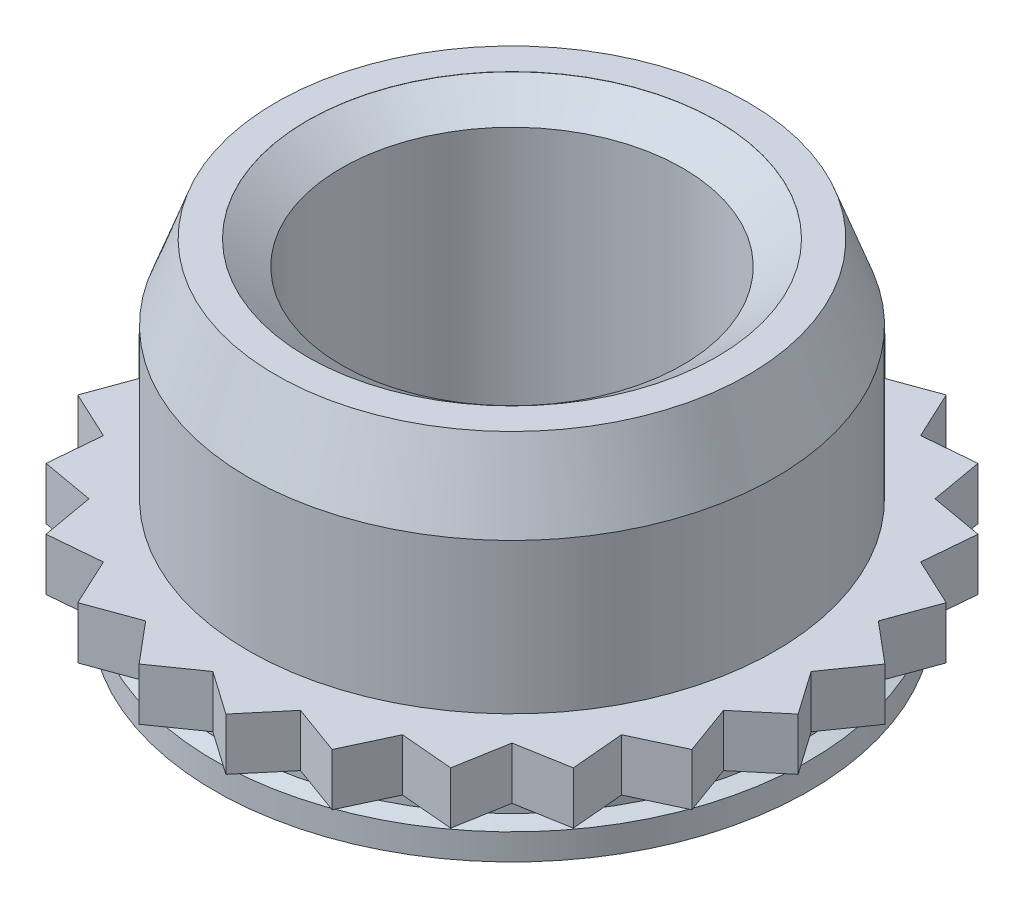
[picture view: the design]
ISO-10303-21;
HEADER;
FILE_DESCRIPTION(('STEP AP214'),'2;1');
FILE_NAME('part.step','',(''),(''),'','','');
FILE_SCHEMA(('AUTOMOTIVE_DESIGN { 1 0 10303 214 1 1 1 1 }'));
ENDSEC;
DATA;
#1=APPLICATION_CONTEXT('core data for automotive mechanical design processes');
#2=APPLICATION_PROTOCOL_DEFINITION('international standard','automotive_design',2000,#1);
#3=PRODUCT_CONTEXT('',#1,'mechanical');
#4=PRODUCT('Part','Part','',(#3));
#5=PRODUCT_RELATED_PRODUCT_CATEGORY('part','',(#4));
#6=PRODUCT_DEFINITION_FORMATION('','',#4);
#7=PRODUCT_DEFINITION_CONTEXT('part definition',#1,'design');
#8=PRODUCT_DEFINITION('design','',#6,#7);
#9=PRODUCT_DEFINITION_SHAPE('','',#8);
#10=(LENGTH_UNIT() NAMED_UNIT(*) SI_UNIT(.MILLI.,.METRE.));
#11=(NAMED_UNIT(*) PLANE_ANGLE_UNIT() SI_UNIT($,.RADIAN.));
#12=(NAMED_UNIT(*) SI_UNIT($,.STERADIAN.) SOLID_ANGLE_UNIT());
#13=UNCERTAINTY_MEASURE_WITH_UNIT(LENGTH_MEASURE(1.E-05),#10,'distance_accuracy_value','');
#14=(GEOMETRIC_REPRESENTATION_CONTEXT(3) GLOBAL_UNCERTAINTY_ASSIGNED_CONTEXT((#13)) GLOBAL_UNIT_ASSIGNED_CONTEXT((#10,
#11,#12)) REPRESENTATION_CONTEXT('',''));
#15=CARTESIAN_POINT('',(0.,0.,0.));
#16=DIRECTION('',(0.,0.,1.));
#17=DIRECTION('',(1.,0.,0.));
#18=AXIS2_PLACEMENT_3D('',#15,#16,#17);
#19=CARTESIAN_POINT('',(0.,0.,0.));
#20=DIRECTION('',(0.,-1.,0.));
#21=DIRECTION('',(0.,0.,-1.));
#22=AXIS2_PLACEMENT_3D('',#19,#20,#21);
#23=CYLINDRICAL_SURFACE('',#22,3.86);
#24=CARTESIAN_POINT('',(0.,2.2,0.));
#25=DIRECTION('',(0.,-1.,0.));
#26=DIRECTION('',(0.,0.,-1.));
#27=AXIS2_PLACEMENT_3D('',#24,#25,#26);
#28=CIRCLE('',#27,3.86);
#29=CARTESIAN_POINT('',(0.,2.2,-3.86));
#30=VERTEX_POINT('',#29);
#31=EDGE_CURVE('E747',#30,#30,#28,.T.);
#32=ORIENTED_EDGE('',*,*,#31,.T.);
#33=EDGE_LOOP('',(#32));
#34=FACE_BOUND('',#33,.T.);
#35=CARTESIAN_POINT('',(0.,0.,0.));
#36=DIRECTION('',(0.,-1.,0.));
#37=DIRECTION('',(0.,0.,-1.));
#38=AXIS2_PLACEMENT_3D('',#35,#36,#37);
#39=CIRCLE('',#38,3.86);
#40=CARTESIAN_POINT('',(0.,0.,-3.86));
#41=VERTEX_POINT('',#40);
#42=EDGE_CURVE('E11',#41,#41,#39,.T.);
#43=ORIENTED_EDGE('',*,*,#42,.F.);
#44=EDGE_LOOP('',(#43));
#45=FACE_BOUND('',#44,.T.);
#46=ADVANCED_FACE('F39',(#34,#45),#23,.T.);
#47=CARTESIAN_POINT('',(4.87,0.,0.));
#48=DIRECTION('',(0.,1.,0.));
#49=DIRECTION('',(0.,0.,1.));
#50=AXIS2_PLACEMENT_3D('',#47,#48,#49);
#51=PLANE('',#50);
#52=DIRECTION('',(0.642592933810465,0.,0.766207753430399));
#53=VECTOR('',#52,1.);
#54=CARTESIAN_POINT('',(-0.635662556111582,0.,4.82833647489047));
#55=LINE('',#54,#53);
#56=CARTESIAN_POINT('',(-1.13440387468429,0.,4.233652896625));
#57=VERTEX_POINT('',#56);
#58=CARTESIAN_POINT('',(-0.635662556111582,0.,4.82833647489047));
#59=VERTEX_POINT('',#58);
#60=EDGE_CURVE('E349',#57,#59,#55,.T.);
#61=ORIENTED_EDGE('',*,*,#60,.T.);
#62=DIRECTION('',(0.819006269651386,0.,-0.573784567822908));
#63=VECTOR('',#62,1.);
#64=CARTESIAN_POINT('',(0.,0.,4.383));
#65=LINE('',#64,#63);
#66=CARTESIAN_POINT('',(0.,0.,4.383));
#67=VERTEX_POINT('',#66);
#68=EDGE_CURVE('E717',#59,#67,#65,.T.);
#69=ORIENTED_EDGE('',*,*,#68,.T.);
#70=DIRECTION('',(0.819006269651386,0.,0.573784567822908));
#71=VECTOR('',#70,1.);
#72=CARTESIAN_POINT('',(0.635662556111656,0.,4.82833647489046));
#73=LINE('',#72,#71);
#74=CARTESIAN_POINT('',(0.635662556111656,0.,4.82833647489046));
#75=VERTEX_POINT('',#74);
#76=EDGE_CURVE('E719',#67,#75,#73,.T.);
#77=ORIENTED_EDGE('',*,*,#76,.T.);
#78=DIRECTION('',(0.642592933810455,0.,-0.766207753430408));
#79=VECTOR('',#78,1.);
#80=CARTESIAN_POINT('',(1.13440387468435,0.,4.23365289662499));
#81=LINE('',#80,#79);
#82=CARTESIAN_POINT('',(1.13440387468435,0.,4.23365289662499));
#83=VERTEX_POINT('',#82);
#84=EDGE_CURVE('E57',#75,#83,#81,.T.);
#85=ORIENTED_EDGE('',*,*,#84,.T.);
#86=DIRECTION('',(0.93960568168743,0.,0.342258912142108));
#87=VECTOR('',#86,1.);
#88=CARTESIAN_POINT('',(1.86366831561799,0.,4.49929332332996));
#89=LINE('',#88,#87);
#90=CARTESIAN_POINT('',(1.86366831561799,0.,4.49929332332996));
#91=VERTEX_POINT('',#90);
#92=EDGE_CURVE('E704',#83,#91,#89,.T.);
#93=ORIENTED_EDGE('',*,*,#92,.T.);
#94=DIRECTION('',(0.422387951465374,0.,-0.906415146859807));
#95=VECTOR('',#94,1.);
#96=CARTESIAN_POINT('',(2.1915,0.,3.79578934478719));
#97=LINE('',#96,#95);
#98=CARTESIAN_POINT('',(2.1915,0.,3.79578934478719));
#99=VERTEX_POINT('',#98);
#100=EDGE_CURVE('E691',#91,#99,#97,.T.);
#101=ORIENTED_EDGE('',*,*,#100,.T.);
#102=DIRECTION('',(0.996172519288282,0.,0.087408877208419));
#103=VECTOR('',#102,1.);
#104=CARTESIAN_POINT('',(2.96466815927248,0.,3.86363076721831));
#105=LINE('',#104,#103);
#106=CARTESIAN_POINT('',(2.96466815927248,0.,3.86363076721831));
#107=VERTEX_POINT('',#106);
#108=EDGE_CURVE('E688',#99,#107,#105,.T.);
#109=ORIENTED_EDGE('',*,*,#108,.T.);
#110=DIRECTION('',(0.173397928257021,0.,-0.984851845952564));
#111=VECTOR('',#110,1.);
#112=CARTESIAN_POINT('',(3.09924902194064,0.,3.09924902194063));
#113=LINE('',#112,#111);
#114=CARTESIAN_POINT('',(3.09924902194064,0.,3.09924902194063));
#115=VERTEX_POINT('',#114);
#116=EDGE_CURVE('E675',#107,#115,#113,.T.);
#117=ORIENTED_EDGE('',*,*,#116,.T.);
#118=DIRECTION('',(0.984851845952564,0.,-0.173397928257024));
#119=VECTOR('',#118,1.);
#120=CARTESIAN_POINT('',(3.86363076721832,0.,2.96466815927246));
#121=LINE('',#120,#119);
#122=CARTESIAN_POINT('',(3.86363076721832,0.,2.96466815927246));
#123=VERTEX_POINT('',#122);
#124=EDGE_CURVE('E674',#115,#123,#121,.T.);
#125=ORIENTED_EDGE('',*,*,#124,.T.);
#126=DIRECTION('',(-0.0874088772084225,0.,-0.996172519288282));
#127=VECTOR('',#126,1.);
#128=CARTESIAN_POINT('',(3.7957893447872,0.,2.19149999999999));
#129=LINE('',#128,#127);
#130=CARTESIAN_POINT('',(3.7957893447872,0.,2.19149999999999));
#131=VERTEX_POINT('',#130);
#132=EDGE_CURVE('E659',#123,#131,#129,.T.);
#133=ORIENTED_EDGE('',*,*,#132,.T.);
#134=DIRECTION('',(0.906415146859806,0.,-0.422387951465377));
#135=VECTOR('',#134,1.);
#136=CARTESIAN_POINT('',(4.49929332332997,0.,1.86366831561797));
#137=LINE('',#136,#135);
#138=CARTESIAN_POINT('',(4.49929332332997,0.,1.86366831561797));
#139=VERTEX_POINT('',#138);
#140=EDGE_CURVE('E658',#131,#139,#137,.T.);
#141=ORIENTED_EDGE('',*,*,#140,.T.);
#142=DIRECTION('',(-0.342258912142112,0.,-0.939605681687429));
#143=VECTOR('',#142,1.);
#144=CARTESIAN_POINT('',(4.23365289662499,0.,1.13440387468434));
#145=LINE('',#144,#143);
#146=CARTESIAN_POINT('',(4.23365289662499,0.,1.13440387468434));
#147=VERTEX_POINT('',#146);
#148=EDGE_CURVE('E639',#139,#147,#145,.T.);
#149=ORIENTED_EDGE('',*,*,#148,.T.);
#150=DIRECTION('',(0.766207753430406,0.,-0.642592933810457));
#151=VECTOR('',#150,1.);
#152=CARTESIAN_POINT('',(4.82833647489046,0.,0.635662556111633));
#153=LINE('',#152,#151);
#154=CARTESIAN_POINT('',(4.82833647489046,0.,0.635662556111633));
#155=VERTEX_POINT('',#154);
#156=EDGE_CURVE('E644',#147,#155,#153,.T.);
#157=ORIENTED_EDGE('',*,*,#156,.T.);
#158=DIRECTION('',(-0.573784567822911,0.,-0.819006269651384));
#159=VECTOR('',#158,1.);
#160=CARTESIAN_POINT('',(4.383,0.,0.));
#161=LINE('',#160,#159);
#162=CARTESIAN_POINT('',(4.383,0.,0.));
#163=VERTEX_POINT('',#162);
#164=EDGE_CURVE('E624',#155,#163,#161,.T.);
#165=ORIENTED_EDGE('',*,*,#164,.T.);
#166=DIRECTION('',(0.573784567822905,0.,-0.819006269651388));
#167=VECTOR('',#166,1.);
#168=CARTESIAN_POINT('',(4.82833647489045,0.,-0.635662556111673));
#169=LINE('',#168,#167);
#170=CARTESIAN_POINT('',(4.82833647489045,0.,-0.635662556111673));
#171=VERTEX_POINT('',#170);
#172=EDGE_CURVE('E630',#163,#171,#169,.T.);
#173=ORIENTED_EDGE('',*,*,#172,.T.);
#174=DIRECTION('',(-0.76620775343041,0.,-0.642592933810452));
#175=VECTOR('',#174,1.);
#176=CARTESIAN_POINT('',(4.23365289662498,0.,-1.13440387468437));
#177=LINE('',#176,#175);
#178=CARTESIAN_POINT('',(4.23365289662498,0.,-1.13440387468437));
#179=VERTEX_POINT('',#178);
#180=EDGE_CURVE('E607',#171,#179,#177,.T.);
#181=ORIENTED_EDGE('',*,*,#180,.T.);
#182=DIRECTION('',(0.342258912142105,0.,-0.939605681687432));
#183=VECTOR('',#182,1.);
#184=CARTESIAN_POINT('',(4.49929332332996,0.,-1.86366831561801));
#185=LINE('',#184,#183);
#186=CARTESIAN_POINT('',(4.49929332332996,0.,-1.86366831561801));
#187=VERTEX_POINT('',#186);
#188=EDGE_CURVE('E614',#179,#187,#185,.T.);
#189=ORIENTED_EDGE('',*,*,#188,.T.);
#190=DIRECTION('',(-0.906415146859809,0.,-0.422387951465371));
#191=VECTOR('',#190,1.);
#192=CARTESIAN_POINT('',(3.79578934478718,0.,-2.19150000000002));
#193=LINE('',#192,#191);
#194=CARTESIAN_POINT('',(3.79578934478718,0.,-2.19150000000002));
#195=VERTEX_POINT('',#194);
#196=EDGE_CURVE('E591',#187,#195,#193,.T.);
#197=ORIENTED_EDGE('',*,*,#196,.T.);
#198=DIRECTION('',(0.0874088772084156,0.,-0.996172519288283));
#199=VECTOR('',#198,1.);
#200=CARTESIAN_POINT('',(3.8636307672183,0.,-2.96466815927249));
#201=LINE('',#200,#199);
#202=CARTESIAN_POINT('',(3.8636307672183,0.,-2.96466815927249));
#203=VERTEX_POINT('',#202);
#204=EDGE_CURVE('E592',#195,#203,#201,.T.);
#205=ORIENTED_EDGE('',*,*,#204,.T.);
#206=DIRECTION('',(-0.984851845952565,0.,-0.173397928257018));
#207=VECTOR('',#206,1.);
#208=CARTESIAN_POINT('',(3.09924902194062,0.,-3.09924902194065));
#209=LINE('',#208,#207);
#210=CARTESIAN_POINT('',(3.09924902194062,0.,-3.09924902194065));
#211=VERTEX_POINT('',#210);
#212=EDGE_CURVE('E577',#203,#211,#209,.T.);
#213=ORIENTED_EDGE('',*,*,#212,.T.);
#214=DIRECTION('',(-0.173397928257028,0.,-0.984851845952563));
#215=VECTOR('',#214,1.);
#216=CARTESIAN_POINT('',(2.96466815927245,0.,-3.86363076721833));
#217=LINE('',#216,#215);
#218=CARTESIAN_POINT('',(2.96466815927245,0.,-3.86363076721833));
#219=VERTEX_POINT('',#218);
#220=EDGE_CURVE('E576',#211,#219,#217,.T.);
#221=ORIENTED_EDGE('',*,*,#220,.T.);
#222=DIRECTION('',(-0.996172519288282,0.,0.0874088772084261));
#223=VECTOR('',#222,1.);
#224=CARTESIAN_POINT('',(2.19149999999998,0.,-3.79578934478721));
#225=LINE('',#224,#223);
#226=CARTESIAN_POINT('',(2.19149999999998,0.,-3.79578934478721));
#227=VERTEX_POINT('',#226);
#228=EDGE_CURVE('E557',#219,#227,#225,.T.);
#229=ORIENTED_EDGE('',*,*,#228,.T.);
#230=DIRECTION('',(-0.42238795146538,0.,-0.906415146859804));
#231=VECTOR('',#230,1.);
#232=CARTESIAN_POINT('',(1.86366831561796,0.,-4.49929332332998));
#233=LINE('',#232,#231);
#234=CARTESIAN_POINT('',(1.86366831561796,0.,-4.49929332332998));
#235=VERTEX_POINT('',#234);
#236=EDGE_CURVE('E563',#227,#235,#233,.T.);
#237=ORIENTED_EDGE('',*,*,#236,.T.);
#238=DIRECTION('',(-0.939605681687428,0.,0.342258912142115));
#239=VECTOR('',#238,1.);
#240=CARTESIAN_POINT('',(1.13440387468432,0.,-4.23365289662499));
#241=LINE('',#240,#239);
#242=CARTESIAN_POINT('',(1.13440387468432,0.,-4.23365289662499));
#243=VERTEX_POINT('',#242);
#244=EDGE_CURVE('E543',#235,#243,#241,.T.);
#245=ORIENTED_EDGE('',*,*,#244,.T.);
#246=DIRECTION('',(-0.64259293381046,0.,-0.766207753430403));
#247=VECTOR('',#246,1.);
#248=CARTESIAN_POINT('',(0.635662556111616,0.,-4.82833647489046));
#249=LINE('',#248,#247);
#250=CARTESIAN_POINT('',(0.635662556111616,0.,-4.82833647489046));
#251=VERTEX_POINT('',#250);
#252=EDGE_CURVE('E546',#243,#251,#249,.T.);
#253=ORIENTED_EDGE('',*,*,#252,.T.);
#254=DIRECTION('',(-0.819006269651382,0.,0.573784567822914));
#255=VECTOR('',#254,1.);
#256=CARTESIAN_POINT('',(0.,0.,-4.383));
#257=LINE('',#256,#255);
#258=CARTESIAN_POINT('',(0.,0.,-4.383));
#259=VERTEX_POINT('',#258);
#260=EDGE_CURVE('E530',#251,#259,#257,.T.);
#261=ORIENTED_EDGE('',*,*,#260,.T.);
#262=DIRECTION('',(-0.81900626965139,0.,-0.573784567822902));
#263=VECTOR('',#262,1.);
#264=CARTESIAN_POINT('',(-0.63566255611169,0.,-4.82833647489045));
#265=LINE('',#264,#263);
#266=CARTESIAN_POINT('',(-0.63566255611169,0.,-4.82833647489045));
#267=VERTEX_POINT('',#266);
#268=EDGE_CURVE('E532',#259,#267,#265,.T.);
#269=ORIENTED_EDGE('',*,*,#268,.T.);
#270=DIRECTION('',(-0.642592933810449,0.,0.766207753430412));
#271=VECTOR('',#270,1.);
#272=CARTESIAN_POINT('',(-1.13440387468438,0.,-4.23365289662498));
#273=LINE('',#272,#271);
#274=CARTESIAN_POINT('',(-1.13440387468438,0.,-4.23365289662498));
#275=VERTEX_POINT('',#274);
#276=EDGE_CURVE('E515',#267,#275,#273,.T.);
#277=ORIENTED_EDGE('',*,*,#276,.T.);
#278=DIRECTION('',(-0.939605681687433,0.,-0.342258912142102));
#279=VECTOR('',#278,1.);
#280=CARTESIAN_POINT('',(-1.86366831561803,0.,-4.49929332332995));
#281=LINE('',#280,#279);
#282=CARTESIAN_POINT('',(-1.86366831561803,0.,-4.49929332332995));
#283=VERTEX_POINT('',#282);
#284=EDGE_CURVE('E513',#275,#283,#281,.T.);
#285=ORIENTED_EDGE('',*,*,#284,.T.);
#286=DIRECTION('',(-0.422387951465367,0.,0.90641514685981));
#287=VECTOR('',#286,1.);
#288=CARTESIAN_POINT('',(-2.19150000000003,0.,-3.79578934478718));
#289=LINE('',#288,#287);
#290=CARTESIAN_POINT('',(-2.19150000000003,0.,-3.79578934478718));
#291=VERTEX_POINT('',#290);
#292=EDGE_CURVE('E496',#283,#291,#289,.T.);
#293=ORIENTED_EDGE('',*,*,#292,.T.);
#294=DIRECTION('',(-0.996172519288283,0.,-0.0874088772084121));
#295=VECTOR('',#294,1.);
#296=CARTESIAN_POINT('',(-2.96466815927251,0.,-3.86363076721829));
#297=LINE('',#296,#295);
#298=CARTESIAN_POINT('',(-2.96466815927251,0.,-3.86363076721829));
#299=VERTEX_POINT('',#298);
#300=EDGE_CURVE('E497',#291,#299,#297,.T.);
#301=ORIENTED_EDGE('',*,*,#300,.T.);
#302=DIRECTION('',(-0.173397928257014,0.,0.984851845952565));
#303=VECTOR('',#302,1.);
#304=CARTESIAN_POINT('',(-3.09924902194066,0.,-3.09924902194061));
#305=LINE('',#304,#303);
#306=CARTESIAN_POINT('',(-3.09924902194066,0.,-3.09924902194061));
#307=VERTEX_POINT('',#306);
#308=EDGE_CURVE('E479',#299,#307,#305,.T.);
#309=ORIENTED_EDGE('',*,*,#308,.T.);
#310=DIRECTION('',(-0.984851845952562,0.,0.173397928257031));
#311=VECTOR('',#310,1.);
#312=CARTESIAN_POINT('',(-3.86363076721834,0.,-2.96466815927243));
#313=LINE('',#312,#311);
#314=CARTESIAN_POINT('',(-3.86363076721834,0.,-2.96466815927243));
#315=VERTEX_POINT('',#314);
#316=EDGE_CURVE('E485',#307,#315,#313,.T.);
#317=ORIENTED_EDGE('',*,*,#316,.T.);
#318=DIRECTION('',(0.0874088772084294,0.,0.996172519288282));
#319=VECTOR('',#318,1.);
#320=CARTESIAN_POINT('',(-3.79578934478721,0.,-2.19149999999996));
#321=LINE('',#320,#319);
#322=CARTESIAN_POINT('',(-3.79578934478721,0.,-2.19149999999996));
#323=VERTEX_POINT('',#322);
#324=EDGE_CURVE('E463',#315,#323,#321,.T.);
#325=ORIENTED_EDGE('',*,*,#324,.T.);
#326=DIRECTION('',(-0.906415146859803,0.,0.422387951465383));
#327=VECTOR('',#326,1.);
#328=CARTESIAN_POINT('',(-4.49929332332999,0.,-1.86366831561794));
#329=LINE('',#328,#327);
#330=CARTESIAN_POINT('',(-4.49929332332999,0.,-1.86366831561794));
#331=VERTEX_POINT('',#330);
#332=EDGE_CURVE('E470',#323,#331,#329,.T.);
#333=ORIENTED_EDGE('',*,*,#332,.T.);
#334=DIRECTION('',(0.342258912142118,0.,0.939605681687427));
#335=VECTOR('',#334,1.);
#336=CARTESIAN_POINT('',(-4.233652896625,0.,-1.13440387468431));
#337=LINE('',#336,#335);
#338=CARTESIAN_POINT('',(-4.233652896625,0.,-1.13440387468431));
#339=VERTEX_POINT('',#338);
#340=EDGE_CURVE('E449',#331,#339,#337,.T.);
#341=ORIENTED_EDGE('',*,*,#340,.T.);
#342=DIRECTION('',(-0.766207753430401,0.,0.642592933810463));
#343=VECTOR('',#342,1.);
#344=CARTESIAN_POINT('',(-4.82833647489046,0.,-0.635662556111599));
#345=LINE('',#344,#343);
#346=CARTESIAN_POINT('',(-4.82833647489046,0.,-0.635662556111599));
#347=VERTEX_POINT('',#346);
#348=EDGE_CURVE('E451',#339,#347,#345,.T.);
#349=ORIENTED_EDGE('',*,*,#348,.T.);
#350=DIRECTION('',(0.573784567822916,0.,0.81900626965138));
#351=VECTOR('',#350,1.);
#352=CARTESIAN_POINT('',(-4.383,0.,0.));
#353=LINE('',#352,#351);
#354=CARTESIAN_POINT('',(-4.383,0.,0.));
#355=VERTEX_POINT('',#354);
#356=EDGE_CURVE('E435',#347,#355,#353,.T.);
#357=ORIENTED_EDGE('',*,*,#356,.T.);
#358=DIRECTION('',(-0.573784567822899,0.,0.819006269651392));
#359=VECTOR('',#358,1.);
#360=CARTESIAN_POINT('',(-4.82833647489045,0.,0.635662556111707));
#361=LINE('',#360,#359);
#362=CARTESIAN_POINT('',(-4.82833647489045,0.,0.635662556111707));
#363=VERTEX_POINT('',#362);
#364=EDGE_CURVE('E434',#355,#363,#361,.T.);
#365=ORIENTED_EDGE('',*,*,#364,.T.);
#366=DIRECTION('',(0.766207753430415,0.,0.642592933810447));
#367=VECTOR('',#366,1.);
#368=CARTESIAN_POINT('',(-4.23365289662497,0.,1.1344038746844));
#369=LINE('',#368,#367);
#370=CARTESIAN_POINT('',(-4.23365289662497,0.,1.1344038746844));
#371=VERTEX_POINT('',#370);
#372=EDGE_CURVE('E419',#363,#371,#369,.T.);
#373=ORIENTED_EDGE('',*,*,#372,.T.);
#374=DIRECTION('',(-0.342258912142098,0.,0.939605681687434));
#375=VECTOR('',#374,1.);
#376=CARTESIAN_POINT('',(-4.49929332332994,0.,1.86366831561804));
#377=LINE('',#376,#375);
#378=CARTESIAN_POINT('',(-4.49929332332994,0.,1.86366831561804));
#379=VERTEX_POINT('',#378);
#380=EDGE_CURVE('E418',#371,#379,#377,.T.);
#381=ORIENTED_EDGE('',*,*,#380,.T.);
#382=DIRECTION('',(0.906415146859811,0.,0.422387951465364));
#383=VECTOR('',#382,1.);
#384=CARTESIAN_POINT('',(-3.79578934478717,0.,2.19150000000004));
#385=LINE('',#384,#383);
#386=CARTESIAN_POINT('',(-3.79578934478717,0.,2.19150000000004));
#387=VERTEX_POINT('',#386);
#388=EDGE_CURVE('E397',#379,#387,#385,.T.);
#389=ORIENTED_EDGE('',*,*,#388,.T.);
#390=DIRECTION('',(-0.0874088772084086,0.,0.996172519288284));
#391=VECTOR('',#390,1.);
#392=CARTESIAN_POINT('',(-3.86363076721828,0.,2.96466815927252));
#393=LINE('',#392,#391);
#394=CARTESIAN_POINT('',(-3.86363076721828,0.,2.96466815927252));
#395=VERTEX_POINT('',#394);
#396=EDGE_CURVE('E401',#387,#395,#393,.T.);
#397=ORIENTED_EDGE('',*,*,#396,.T.);
#398=DIRECTION('',(0.984851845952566,0.,0.173397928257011));
#399=VECTOR('',#398,1.);
#400=CARTESIAN_POINT('',(-3.0992490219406,0.,3.09924902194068));
#401=LINE('',#400,#399);
#402=CARTESIAN_POINT('',(-3.0992490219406,0.,3.09924902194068));
#403=VERTEX_POINT('',#402);
#404=EDGE_CURVE('E381',#395,#403,#401,.T.);
#405=ORIENTED_EDGE('',*,*,#404,.T.);
#406=DIRECTION('',(0.173397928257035,0.,0.984851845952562));
#407=VECTOR('',#406,1.);
#408=CARTESIAN_POINT('',(-2.96466815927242,0.,3.86363076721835));
#409=LINE('',#408,#407);
#410=CARTESIAN_POINT('',(-2.96466815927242,0.,3.86363076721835));
#411=VERTEX_POINT('',#410);
#412=EDGE_CURVE('E387',#403,#411,#409,.T.);
#413=ORIENTED_EDGE('',*,*,#412,.T.);
#414=DIRECTION('',(0.996172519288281,0.,-0.087408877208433));
#415=VECTOR('',#414,1.);
#416=CARTESIAN_POINT('',(-2.19149999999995,0.,3.79578934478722));
#417=LINE('',#416,#415);
#418=CARTESIAN_POINT('',(-2.19149999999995,0.,3.79578934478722));
#419=VERTEX_POINT('',#418);
#420=EDGE_CURVE('E371',#411,#419,#417,.T.);
#421=ORIENTED_EDGE('',*,*,#420,.T.);
#422=DIRECTION('',(0.422387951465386,0.,0.906415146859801));
#423=VECTOR('',#422,1.);
#424=CARTESIAN_POINT('',(-1.86366831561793,0.,4.49929332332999));
#425=LINE('',#424,#423);
#426=CARTESIAN_POINT('',(-1.86366831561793,0.,4.49929332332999));
#427=VERTEX_POINT('',#426);
#428=EDGE_CURVE('E362',#419,#427,#425,.T.);
#429=ORIENTED_EDGE('',*,*,#428,.T.);
#430=DIRECTION('',(0.939605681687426,0.,-0.342258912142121));
#431=VECTOR('',#430,1.);
#432=CARTESIAN_POINT('',(-1.13440387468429,0.,4.233652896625));
#433=LINE('',#432,#431);
#434=EDGE_CURVE('E344',#427,#57,#433,.T.);
#435=ORIENTED_EDGE('',*,*,#434,.T.);
#436=EDGE_LOOP('',(#61,#69,#77,#85,#93,#101,#109,#117,#125,#133,#141,#149,#157,#165,#173,#181,
#189,#197,#205,#213,#221,#229,#237,#245,#253,#261,#269,#277,#285,#293,#301,#309,#317,#325,#333,
#341,#349,#357,#365,#373,#381,#389,#397,#405,#413,#421,#429,#435));
#437=FACE_BOUND('',#436,.T.);
#438=ORIENTED_EDGE('',*,*,#42,.T.);
#439=EDGE_LOOP('',(#438));
#440=FACE_BOUND('',#439,.T.);
#441=ADVANCED_FACE('F363',(#437,#440),#51,.T.);
#442=CARTESIAN_POINT('',(4.13725,-0.765,0.));
#443=DIRECTION('',(0.,-1.,0.));
#444=DIRECTION('',(0.,0.,-1.));
#445=AXIS2_PLACEMENT_3D('',#442,#443,#444);
#446=PLANE('',#445);
#447=DIRECTION('',(0.642592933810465,0.,0.766207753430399));
#448=VECTOR('',#447,1.);
#449=CARTESIAN_POINT('',(-0.635662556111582,-0.765,4.82833647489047));
#450=LINE('',#449,#448);
#451=CARTESIAN_POINT('',(-1.13440387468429,-0.765,4.233652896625));
#452=VERTEX_POINT('',#451);
#453=CARTESIAN_POINT('',(-0.635662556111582,-0.765,4.82833647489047));
#454=VERTEX_POINT('',#453);
#455=EDGE_CURVE('E366',#452,#454,#450,.T.);
#456=ORIENTED_EDGE('',*,*,#455,.F.);
#457=DIRECTION('',(0.939605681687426,0.,-0.342258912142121));
#458=VECTOR('',#457,1.);
#459=CARTESIAN_POINT('',(-1.13440387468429,-0.765,4.233652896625));
#460=LINE('',#459,#458);
#461=CARTESIAN_POINT('',(-1.86366831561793,-0.765,4.49929332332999));
#462=VERTEX_POINT('',#461);
#463=EDGE_CURVE('E346',#462,#452,#460,.T.);
#464=ORIENTED_EDGE('',*,*,#463,.F.);
#465=DIRECTION('',(0.422387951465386,0.,0.906415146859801));
#466=VECTOR('',#465,1.);
#467=CARTESIAN_POINT('',(-1.86366831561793,-0.765,4.49929332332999));
#468=LINE('',#467,#466);
#469=CARTESIAN_POINT('',(-2.19149999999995,-0.765,3.79578934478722));
#470=VERTEX_POINT('',#469);
#471=EDGE_CURVE('E373',#470,#462,#468,.T.);
#472=ORIENTED_EDGE('',*,*,#471,.F.);
#473=DIRECTION('',(0.996172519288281,0.,-0.087408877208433));
#474=VECTOR('',#473,1.);
#475=CARTESIAN_POINT('',(-2.19149999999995,-0.765,3.79578934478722));
#476=LINE('',#475,#474);
#477=CARTESIAN_POINT('',(-2.96466815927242,-0.765,3.86363076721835));
#478=VERTEX_POINT('',#477);
#479=EDGE_CURVE('E348',#478,#470,#476,.T.);
#480=ORIENTED_EDGE('',*,*,#479,.F.);
#481=DIRECTION('',(0.173397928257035,0.,0.984851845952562));
#482=VECTOR('',#481,1.);
#483=CARTESIAN_POINT('',(-2.96466815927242,-0.765,3.86363076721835));
#484=LINE('',#483,#482);
#485=CARTESIAN_POINT('',(-3.0992490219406,-0.765,3.09924902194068));
#486=VERTEX_POINT('',#485);
#487=EDGE_CURVE('E389',#486,#478,#484,.T.);
#488=ORIENTED_EDGE('',*,*,#487,.F.);
#489=DIRECTION('',(0.984851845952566,0.,0.173397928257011));
#490=VECTOR('',#489,1.);
#491=CARTESIAN_POINT('',(-3.0992490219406,-0.765,3.09924902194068));
#492=LINE('',#491,#490);
#493=CARTESIAN_POINT('',(-3.86363076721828,-0.765,2.96466815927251));
#494=VERTEX_POINT('',#493);
#495=EDGE_CURVE('E385',#494,#486,#492,.T.);
#496=ORIENTED_EDGE('',*,*,#495,.F.);
#497=DIRECTION('',(-0.0874088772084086,0.,0.996172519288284));
#498=VECTOR('',#497,1.);
#499=CARTESIAN_POINT('',(-3.86363076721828,-0.765,2.96466815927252));
#500=LINE('',#499,#498);
#501=CARTESIAN_POINT('',(-3.79578934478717,-0.765,2.19150000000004));
#502=VERTEX_POINT('',#501);
#503=EDGE_CURVE('E404',#502,#494,#500,.T.);
#504=ORIENTED_EDGE('',*,*,#503,.F.);
#505=DIRECTION('',(0.906415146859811,0.,0.422387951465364));
#506=VECTOR('',#505,1.);
#507=CARTESIAN_POINT('',(-3.79578934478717,-0.765,2.19150000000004));
#508=LINE('',#507,#506);
#509=CARTESIAN_POINT('',(-4.49929332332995,-0.765,1.86366831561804));
#510=VERTEX_POINT('',#509);
#511=EDGE_CURVE('E400',#510,#502,#508,.T.);
#512=ORIENTED_EDGE('',*,*,#511,.F.);
#513=DIRECTION('',(-0.342258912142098,0.,0.939605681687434));
#514=VECTOR('',#513,1.);
#515=CARTESIAN_POINT('',(-4.49929332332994,-0.765,1.86366831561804));
#516=LINE('',#515,#514);
#517=CARTESIAN_POINT('',(-4.23365289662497,-0.765,1.1344038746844));
#518=VERTEX_POINT('',#517);
#519=EDGE_CURVE('E417',#518,#510,#516,.T.);
#520=ORIENTED_EDGE('',*,*,#519,.F.);
#521=DIRECTION('',(0.766207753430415,0.,0.642592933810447));
#522=VECTOR('',#521,1.);
#523=CARTESIAN_POINT('',(-4.23365289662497,-0.765,1.1344038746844));
#524=LINE('',#523,#522);
#525=CARTESIAN_POINT('',(-4.82833647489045,-0.765,0.6356625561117));
#526=VERTEX_POINT('',#525);
#527=EDGE_CURVE('E413',#526,#518,#524,.T.);
#528=ORIENTED_EDGE('',*,*,#527,.F.);
#529=DIRECTION('',(-0.573784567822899,0.,0.819006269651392));
#530=VECTOR('',#529,1.);
#531=CARTESIAN_POINT('',(-4.82833647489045,-0.765,0.635662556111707));
#532=LINE('',#531,#530);
#533=CARTESIAN_POINT('',(-4.383,-0.765,0.));
#534=VERTEX_POINT('',#533);
#535=EDGE_CURVE('E436',#534,#526,#532,.T.);
#536=ORIENTED_EDGE('',*,*,#535,.F.);
#537=DIRECTION('',(0.573784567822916,0.,0.81900626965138));
#538=VECTOR('',#537,1.);
#539=CARTESIAN_POINT('',(-4.383,-0.765,0.));
#540=LINE('',#539,#538);
#541=CARTESIAN_POINT('',(-4.82833647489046,-0.765,-0.635662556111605));
#542=VERTEX_POINT('',#541);
#543=EDGE_CURVE('E427',#542,#534,#540,.T.);
#544=ORIENTED_EDGE('',*,*,#543,.F.);
#545=DIRECTION('',(-0.766207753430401,0.,0.642592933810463));
#546=VECTOR('',#545,1.);
#547=CARTESIAN_POINT('',(-4.82833647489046,-0.765,-0.635662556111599));
#548=LINE('',#547,#546);
#549=CARTESIAN_POINT('',(-4.233652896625,-0.765,-1.13440387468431));
#550=VERTEX_POINT('',#549);
#551=EDGE_CURVE('E452',#550,#542,#548,.T.);
#552=ORIENTED_EDGE('',*,*,#551,.F.);
#553=DIRECTION('',(0.342258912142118,0.,0.939605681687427));
#554=VECTOR('',#553,1.);
#555=CARTESIAN_POINT('',(-4.233652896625,-0.765,-1.13440387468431));
#556=LINE('',#555,#554);
#557=CARTESIAN_POINT('',(-4.49929332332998,-0.765,-1.86366831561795));
#558=VERTEX_POINT('',#557);
#559=EDGE_CURVE('E447',#558,#550,#556,.T.);
#560=ORIENTED_EDGE('',*,*,#559,.F.);
#561=DIRECTION('',(-0.906415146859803,0.,0.422387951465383));
#562=VECTOR('',#561,1.);
#563=CARTESIAN_POINT('',(-4.49929332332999,-0.765,-1.86366831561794));
#564=LINE('',#563,#562);
#565=CARTESIAN_POINT('',(-3.79578934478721,-0.765,-2.19149999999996));
#566=VERTEX_POINT('',#565);
#567=EDGE_CURVE('E466',#566,#558,#564,.T.);
#568=ORIENTED_EDGE('',*,*,#567,.F.);
#569=DIRECTION('',(0.0874088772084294,0.,0.996172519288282));
#570=VECTOR('',#569,1.);
#571=CARTESIAN_POINT('',(-3.79578934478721,-0.765,-2.19149999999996));
#572=LINE('',#571,#570);
#573=CARTESIAN_POINT('',(-3.86363076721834,-0.765,-2.96466815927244));
#574=VERTEX_POINT('',#573);
#575=EDGE_CURVE('E461',#574,#566,#572,.T.);
#576=ORIENTED_EDGE('',*,*,#575,.F.);
#577=DIRECTION('',(-0.984851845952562,0.,0.173397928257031));
#578=VECTOR('',#577,1.);
#579=CARTESIAN_POINT('',(-3.86363076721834,-0.765,-2.96466815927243));
#580=LINE('',#579,#578);
#581=CARTESIAN_POINT('',(-3.09924902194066,-0.765,-3.09924902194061));
#582=VERTEX_POINT('',#581);
#583=EDGE_CURVE('E483',#582,#574,#580,.T.);
#584=ORIENTED_EDGE('',*,*,#583,.F.);
#585=DIRECTION('',(-0.173397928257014,0.,0.984851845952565));
#586=VECTOR('',#585,1.);
#587=CARTESIAN_POINT('',(-3.09924902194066,-0.765,-3.09924902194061));
#588=LINE('',#587,#586);
#589=CARTESIAN_POINT('',(-2.9646681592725,-0.765,-3.86363076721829));
#590=VERTEX_POINT('',#589);
#591=EDGE_CURVE('E477',#590,#582,#588,.T.);
#592=ORIENTED_EDGE('',*,*,#591,.F.);
#593=DIRECTION('',(-0.996172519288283,0.,-0.0874088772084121));
#594=VECTOR('',#593,1.);
#595=CARTESIAN_POINT('',(-2.96466815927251,-0.765,-3.86363076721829));
#596=LINE('',#595,#594);
#597=CARTESIAN_POINT('',(-2.19150000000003,-0.765,-3.79578934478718));
#598=VERTEX_POINT('',#597);
#599=EDGE_CURVE('E499',#598,#590,#596,.T.);
#600=ORIENTED_EDGE('',*,*,#599,.F.);
#601=DIRECTION('',(-0.422387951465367,0.,0.90641514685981));
#602=VECTOR('',#601,1.);
#603=CARTESIAN_POINT('',(-2.19150000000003,-0.765,-3.79578934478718));
#604=LINE('',#603,#602);
#605=CARTESIAN_POINT('',(-1.86366831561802,-0.765,-4.49929332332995));
#606=VERTEX_POINT('',#605);
#607=EDGE_CURVE('E494',#606,#598,#604,.T.);
#608=ORIENTED_EDGE('',*,*,#607,.F.);
#609=DIRECTION('',(-0.939605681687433,0.,-0.342258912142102));
#610=VECTOR('',#609,1.);
#611=CARTESIAN_POINT('',(-1.86366831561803,-0.765,-4.49929332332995));
#612=LINE('',#611,#610);
#613=CARTESIAN_POINT('',(-1.13440387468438,-0.765,-4.23365289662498));
#614=VERTEX_POINT('',#613);
#615=EDGE_CURVE('E516',#614,#606,#612,.T.);
#616=ORIENTED_EDGE('',*,*,#615,.F.);
#617=DIRECTION('',(-0.642592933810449,0.,0.766207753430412));
#618=VECTOR('',#617,1.);
#619=CARTESIAN_POINT('',(-1.13440387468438,-0.765,-4.23365289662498));
#620=LINE('',#619,#618);
#621=CARTESIAN_POINT('',(-0.635662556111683,-0.765,-4.82833647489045));
#622=VERTEX_POINT('',#621);
#623=EDGE_CURVE('E509',#622,#614,#620,.T.);
#624=ORIENTED_EDGE('',*,*,#623,.F.);
#625=DIRECTION('',(-0.81900626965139,0.,-0.573784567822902));
#626=VECTOR('',#625,1.);
#627=CARTESIAN_POINT('',(-0.63566255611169,-0.765,-4.82833647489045));
#628=LINE('',#627,#626);
#629=CARTESIAN_POINT('',(0.,-0.765,-4.383));
#630=VERTEX_POINT('',#629);
#631=EDGE_CURVE('E535',#630,#622,#628,.T.);
#632=ORIENTED_EDGE('',*,*,#631,.F.);
#633=DIRECTION('',(-0.819006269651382,0.,0.573784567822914));
#634=VECTOR('',#633,1.);
#635=CARTESIAN_POINT('',(0.,-0.765,-4.383));
#636=LINE('',#635,#634);
#637=CARTESIAN_POINT('',(0.635662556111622,-0.765,-4.82833647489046));
#638=VERTEX_POINT('',#637);
#639=EDGE_CURVE('E529',#638,#630,#636,.T.);
#640=ORIENTED_EDGE('',*,*,#639,.F.);
#641=DIRECTION('',(-0.64259293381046,0.,-0.766207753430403));
#642=VECTOR('',#641,1.);
#643=CARTESIAN_POINT('',(0.635662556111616,-0.765,-4.82833647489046));
#644=LINE('',#643,#642);
#645=CARTESIAN_POINT('',(1.13440387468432,-0.765,-4.23365289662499));
#646=VERTEX_POINT('',#645);
#647=EDGE_CURVE('E550',#646,#638,#644,.T.);
#648=ORIENTED_EDGE('',*,*,#647,.F.);
#649=DIRECTION('',(-0.939605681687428,0.,0.342258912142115));
#650=VECTOR('',#649,1.);
#651=CARTESIAN_POINT('',(1.13440387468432,-0.765,-4.23365289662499));
#652=LINE('',#651,#650);
#653=CARTESIAN_POINT('',(1.86366831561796,-0.765,-4.49929332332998));
#654=VERTEX_POINT('',#653);
#655=EDGE_CURVE('E545',#654,#646,#652,.T.);
#656=ORIENTED_EDGE('',*,*,#655,.F.);
#657=DIRECTION('',(-0.42238795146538,0.,-0.906415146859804));
#658=VECTOR('',#657,1.);
#659=CARTESIAN_POINT('',(1.86366831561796,-0.765,-4.49929332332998));
#660=LINE('',#659,#658);
#661=CARTESIAN_POINT('',(2.19149999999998,-0.765,-3.79578934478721));
#662=VERTEX_POINT('',#661);
#663=EDGE_CURVE('E562',#662,#654,#660,.T.);
#664=ORIENTED_EDGE('',*,*,#663,.F.);
#665=DIRECTION('',(-0.996172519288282,0.,0.0874088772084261));
#666=VECTOR('',#665,1.);
#667=CARTESIAN_POINT('',(2.19149999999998,-0.765,-3.79578934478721));
#668=LINE('',#667,#666);
#669=CARTESIAN_POINT('',(2.96466815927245,-0.765,-3.86363076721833));
#670=VERTEX_POINT('',#669);
#671=EDGE_CURVE('E556',#670,#662,#668,.T.);
#672=ORIENTED_EDGE('',*,*,#671,.F.);
#673=DIRECTION('',(-0.173397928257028,0.,-0.984851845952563));
#674=VECTOR('',#673,1.);
#675=CARTESIAN_POINT('',(2.96466815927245,-0.765,-3.86363076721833));
#676=LINE('',#675,#674);
#677=CARTESIAN_POINT('',(3.09924902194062,-0.765,-3.09924902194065));
#678=VERTEX_POINT('',#677);
#679=EDGE_CURVE('E578',#678,#670,#676,.T.);
#680=ORIENTED_EDGE('',*,*,#679,.F.);
#681=DIRECTION('',(-0.984851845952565,0.,-0.173397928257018));
#682=VECTOR('',#681,1.);
#683=CARTESIAN_POINT('',(3.09924902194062,-0.765,-3.09924902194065));
#684=LINE('',#683,#682);
#685=CARTESIAN_POINT('',(3.8636307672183,-0.765,-2.96466815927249));
#686=VERTEX_POINT('',#685);
#687=EDGE_CURVE('E573',#686,#678,#684,.T.);
#688=ORIENTED_EDGE('',*,*,#687,.F.);
#689=DIRECTION('',(0.0874088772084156,0.,-0.996172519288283));
#690=VECTOR('',#689,1.);
#691=CARTESIAN_POINT('',(3.8636307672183,-0.765,-2.96466815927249));
#692=LINE('',#691,#690);
#693=CARTESIAN_POINT('',(3.79578934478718,-0.765,-2.19150000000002));
#694=VERTEX_POINT('',#693);
#695=EDGE_CURVE('E597',#694,#686,#692,.T.);
#696=ORIENTED_EDGE('',*,*,#695,.F.);
#697=DIRECTION('',(-0.906415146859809,0.,-0.422387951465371));
#698=VECTOR('',#697,1.);
#699=CARTESIAN_POINT('',(3.79578934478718,-0.765,-2.19150000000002));
#700=LINE('',#699,#698);
#701=CARTESIAN_POINT('',(4.49929332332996,-0.765,-1.863668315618));
#702=VERTEX_POINT('',#701);
#703=EDGE_CURVE('E589',#702,#694,#700,.T.);
#704=ORIENTED_EDGE('',*,*,#703,.F.);
#705=DIRECTION('',(0.342258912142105,0.,-0.939605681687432));
#706=VECTOR('',#705,1.);
#707=CARTESIAN_POINT('',(4.49929332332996,-0.765,-1.86366831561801));
#708=LINE('',#707,#706);
#709=CARTESIAN_POINT('',(4.23365289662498,-0.765,-1.13440387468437));
#710=VERTEX_POINT('',#709);
#711=EDGE_CURVE('E611',#710,#702,#708,.T.);
#712=ORIENTED_EDGE('',*,*,#711,.F.);
#713=DIRECTION('',(-0.76620775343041,0.,-0.642592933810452));
#714=VECTOR('',#713,1.);
#715=CARTESIAN_POINT('',(4.23365289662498,-0.765,-1.13440387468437));
#716=LINE('',#715,#714);
#717=CARTESIAN_POINT('',(4.82833647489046,-0.765,-0.635662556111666));
#718=VERTEX_POINT('',#717);
#719=EDGE_CURVE('E606',#718,#710,#716,.T.);
#720=ORIENTED_EDGE('',*,*,#719,.F.);
#721=DIRECTION('',(0.573784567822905,0.,-0.819006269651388));
#722=VECTOR('',#721,1.);
#723=CARTESIAN_POINT('',(4.82833647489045,-0.765,-0.635662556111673));
#724=LINE('',#723,#722);
#725=CARTESIAN_POINT('',(4.383,-0.765,0.));
#726=VERTEX_POINT('',#725);
#727=EDGE_CURVE('E628',#726,#718,#724,.T.);
#728=ORIENTED_EDGE('',*,*,#727,.F.);
#729=DIRECTION('',(-0.573784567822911,0.,-0.819006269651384));
#730=VECTOR('',#729,1.);
#731=CARTESIAN_POINT('',(4.383,-0.765,0.));
#732=LINE('',#731,#730);
#733=CARTESIAN_POINT('',(4.82833647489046,-0.765,0.635662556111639));
#734=VERTEX_POINT('',#733);
#735=EDGE_CURVE('E625',#734,#726,#732,.T.);
#736=ORIENTED_EDGE('',*,*,#735,.F.);
#737=DIRECTION('',(0.766207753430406,0.,-0.642592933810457));
#738=VECTOR('',#737,1.);
#739=CARTESIAN_POINT('',(4.82833647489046,-0.765,0.635662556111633));
#740=LINE('',#739,#738);
#741=CARTESIAN_POINT('',(4.23365289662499,-0.765,1.13440387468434));
#742=VERTEX_POINT('',#741);
#743=EDGE_CURVE('E641',#742,#734,#740,.T.);
#744=ORIENTED_EDGE('',*,*,#743,.F.);
#745=DIRECTION('',(-0.342258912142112,0.,-0.939605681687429));
#746=VECTOR('',#745,1.);
#747=CARTESIAN_POINT('',(4.23365289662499,-0.765,1.13440387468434));
#748=LINE('',#747,#746);
#749=CARTESIAN_POINT('',(4.49929332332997,-0.765,1.86366831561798));
#750=VERTEX_POINT('',#749);
#751=EDGE_CURVE('E637',#750,#742,#748,.T.);
#752=ORIENTED_EDGE('',*,*,#751,.F.);
#753=DIRECTION('',(0.906415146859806,0.,-0.422387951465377));
#754=VECTOR('',#753,1.);
#755=CARTESIAN_POINT('',(4.49929332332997,-0.765,1.86366831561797));
#756=LINE('',#755,#754);
#757=CARTESIAN_POINT('',(3.7957893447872,-0.765,2.19149999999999));
#758=VERTEX_POINT('',#757);
#759=EDGE_CURVE('E657',#758,#750,#756,.T.);
#760=ORIENTED_EDGE('',*,*,#759,.F.);
#761=DIRECTION('',(-0.0874088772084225,0.,-0.996172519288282));
#762=VECTOR('',#761,1.);
#763=CARTESIAN_POINT('',(3.7957893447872,-0.765,2.19149999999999));
#764=LINE('',#763,#762);
#765=CARTESIAN_POINT('',(3.86363076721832,-0.765,2.96466815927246));
#766=VERTEX_POINT('',#765);
#767=EDGE_CURVE('E653',#766,#758,#764,.T.);
#768=ORIENTED_EDGE('',*,*,#767,.F.);
#769=DIRECTION('',(0.984851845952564,0.,-0.173397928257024));
#770=VECTOR('',#769,1.);
#771=CARTESIAN_POINT('',(3.86363076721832,-0.765,2.96466815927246));
#772=LINE('',#771,#770);
#773=CARTESIAN_POINT('',(3.09924902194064,-0.765,3.09924902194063));
#774=VERTEX_POINT('',#773);
#775=EDGE_CURVE('E679',#774,#766,#772,.T.);
#776=ORIENTED_EDGE('',*,*,#775,.F.);
#777=DIRECTION('',(0.173397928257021,0.,-0.984851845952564));
#778=VECTOR('',#777,1.);
#779=CARTESIAN_POINT('',(3.09924902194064,-0.765,3.09924902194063));
#780=LINE('',#779,#778);
#781=CARTESIAN_POINT('',(2.96466815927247,-0.765,3.86363076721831));
#782=VERTEX_POINT('',#781);
#783=EDGE_CURVE('E670',#782,#774,#780,.T.);
#784=ORIENTED_EDGE('',*,*,#783,.F.);
#785=DIRECTION('',(0.996172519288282,0.,0.087408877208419));
#786=VECTOR('',#785,1.);
#787=CARTESIAN_POINT('',(2.96466815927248,-0.765,3.86363076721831));
#788=LINE('',#787,#786);
#789=CARTESIAN_POINT('',(2.1915,-0.765,3.79578934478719));
#790=VERTEX_POINT('',#789);
#791=EDGE_CURVE('E692',#790,#782,#788,.T.);
#792=ORIENTED_EDGE('',*,*,#791,.F.);
#793=DIRECTION('',(0.422387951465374,0.,-0.906415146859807));
#794=VECTOR('',#793,1.);
#795=CARTESIAN_POINT('',(2.1915,-0.765,3.79578934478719));
#796=LINE('',#795,#794);
#797=CARTESIAN_POINT('',(1.86366831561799,-0.765,4.49929332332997));
#798=VERTEX_POINT('',#797);
#799=EDGE_CURVE('E687',#798,#790,#796,.T.);
#800=ORIENTED_EDGE('',*,*,#799,.F.);
#801=DIRECTION('',(0.93960568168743,0.,0.342258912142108));
#802=VECTOR('',#801,1.);
#803=CARTESIAN_POINT('',(1.86366831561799,-0.765,4.49929332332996));
#804=LINE('',#803,#802);
#805=CARTESIAN_POINT('',(1.13440387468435,-0.765,4.23365289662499));
#806=VERTEX_POINT('',#805);
#807=EDGE_CURVE('E707',#806,#798,#804,.T.);
#808=ORIENTED_EDGE('',*,*,#807,.F.);
#809=DIRECTION('',(0.642592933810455,0.,-0.766207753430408));
#810=VECTOR('',#809,1.);
#811=CARTESIAN_POINT('',(1.13440387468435,-0.765,4.23365289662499));
#812=LINE('',#811,#810);
#813=CARTESIAN_POINT('',(0.63566255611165,-0.765,4.82833647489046));
#814=VERTEX_POINT('',#813);
#815=EDGE_CURVE('E700',#814,#806,#812,.T.);
#816=ORIENTED_EDGE('',*,*,#815,.F.);
#817=DIRECTION('',(0.819006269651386,0.,0.573784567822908));
#818=VECTOR('',#817,1.);
#819=CARTESIAN_POINT('',(0.635662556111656,-0.765,4.82833647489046));
#820=LINE('',#819,#818);
#821=CARTESIAN_POINT('',(0.,-0.765,4.383));
#822=VERTEX_POINT('',#821);
#823=EDGE_CURVE('E724',#822,#814,#820,.T.);
#824=ORIENTED_EDGE('',*,*,#823,.F.);
#825=DIRECTION('',(0.819006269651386,0.,-0.573784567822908));
#826=VECTOR('',#825,1.);
#827=CARTESIAN_POINT('',(0.,-0.765,4.383));
#828=LINE('',#827,#826);
#829=EDGE_CURVE('E716',#454,#822,#828,.T.);
#830=ORIENTED_EDGE('',*,*,#829,.F.);
#831=EDGE_LOOP('',(#456,#464,#472,#480,#488,#496,#504,#512,#520,#528,#536,#544,#552,#560,#568,
#576,#584,#592,#600,#608,#616,#624,#632,#640,#648,#656,#664,#672,#680,#688,#696,#704,#712,#720,
#728,#736,#744,#752,#760,#768,#776,#784,#792,#800,#808,#816,#824,#830));
#832=FACE_BOUND('',#831,.T.);
#833=CARTESIAN_POINT('',(0.,-0.765,0.));
#834=DIRECTION('',(0.,-1.,0.));
#835=DIRECTION('',(0.,0.,-1.));
#836=AXIS2_PLACEMENT_3D('',#833,#834,#835);
#837=CIRCLE('',#836,4.13725);
#838=CARTESIAN_POINT('',(0.,-0.765,-4.13725));
#839=VERTEX_POINT('',#838);
#840=EDGE_CURVE('E48',#839,#839,#837,.T.);
#841=ORIENTED_EDGE('',*,*,#840,.F.);
#842=EDGE_LOOP('',(#841));
#843=FACE_BOUND('',#842,.T.);
#844=ADVANCED_FACE('F794',(#832,#843),#446,.T.);
#845=CARTESIAN_POINT('',(0.,0.,0.));
#846=DIRECTION('',(0.,-1.,0.));
#847=DIRECTION('',(0.,0.,-1.));
#848=AXIS2_PLACEMENT_3D('',#845,#846,#847);
#849=CYLINDRICAL_SURFACE('',#848,4.13725);
#850=ORIENTED_EDGE('',*,*,#840,.T.);
#851=EDGE_LOOP('',(#850));
#852=FACE_BOUND('',#851,.T.);
#853=CARTESIAN_POINT('',(0.,-1.06824548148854,0.));
#854=DIRECTION('',(0.,-1.,0.));
#855=DIRECTION('',(0.,0.,-1.));
#856=AXIS2_PLACEMENT_3D('',#853,#854,#855);
#857=CIRCLE('',#856,4.13725);
#858=CARTESIAN_POINT('',(0.,-1.06824548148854,-4.13725));
#859=VERTEX_POINT('',#858);
#860=EDGE_CURVE('E757',#859,#859,#857,.T.);
#861=ORIENTED_EDGE('',*,*,#860,.F.);
#862=EDGE_LOOP('',(#861));
#863=FACE_BOUND('',#862,.T.);
#864=ADVANCED_FACE('F784',(#852,#863),#849,.T.);
#865=CARTESIAN_POINT('',(0.,-1.1475,0.));
#866=DIRECTION('',(0.,-1.,0.));
#867=DIRECTION('',(0.,0.,-1.));
#868=AXIS2_PLACEMENT_3D('',#865,#866,#867);
#869=CONICAL_SURFACE('',#868,4.355,1.22173047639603);
#870=ORIENTED_EDGE('',*,*,#860,.T.);
#871=EDGE_LOOP('',(#870));
#872=FACE_BOUND('',#871,.T.);
#873=CARTESIAN_POINT('',(0.,-1.1475,0.));
#874=DIRECTION('',(0.,-1.,0.));
#875=DIRECTION('',(0.,0.,-1.));
#876=AXIS2_PLACEMENT_3D('',#873,#874,#875);
#877=CIRCLE('',#876,4.355);
#878=CARTESIAN_POINT('',(0.,-1.1475,-4.355));
#879=VERTEX_POINT('',#878);
#880=EDGE_CURVE('E756',#879,#879,#877,.T.);
#881=ORIENTED_EDGE('',*,*,#880,.F.);
#882=EDGE_LOOP('',(#881));
#883=FACE_BOUND('',#882,.T.);
#884=ADVANCED_FACE('F779',(#872,#883),#869,.T.);
#885=CARTESIAN_POINT('',(0.,0.,0.));
#886=DIRECTION('',(0.,-1.,0.));
#887=DIRECTION('',(0.,0.,-1.));
#888=AXIS2_PLACEMENT_3D('',#885,#886,#887);
#889=CYLINDRICAL_SURFACE('',#888,4.355);
#890=ORIENTED_EDGE('',*,*,#880,.T.);
#891=EDGE_LOOP('',(#890));
#892=FACE_BOUND('',#891,.T.);
#893=CARTESIAN_POINT('',(0.,-1.53,0.));
#894=DIRECTION('',(0.,-1.,0.));
#895=DIRECTION('',(0.,0.,-1.));
#896=AXIS2_PLACEMENT_3D('',#893,#894,#895);
#897=CIRCLE('',#896,4.355);
#898=CARTESIAN_POINT('',(0.,-1.53,-4.355));
#899=VERTEX_POINT('',#898);
#900=EDGE_CURVE('E751',#899,#899,#897,.T.);
#901=ORIENTED_EDGE('',*,*,#900,.F.);
#902=EDGE_LOOP('',(#901));
#903=FACE_BOUND('',#902,.T.);
#904=ADVANCED_FACE('F774',(#892,#903),#889,.T.);
#905=CARTESIAN_POINT('',(2.5,-1.53,0.));
#906=DIRECTION('',(0.,-1.,0.));
#907=DIRECTION('',(0.,0.,-1.));
#908=AXIS2_PLACEMENT_3D('',#905,#906,#907);
#909=PLANE('',#908);
#910=CARTESIAN_POINT('',(0.,-1.53,0.));
#911=DIRECTION('',(0.,-1.,0.));
#912=DIRECTION('',(0.,0.,-1.));
#913=AXIS2_PLACEMENT_3D('',#910,#911,#912);
#914=CIRCLE('',#913,3.);
#915=CARTESIAN_POINT('',(0.,-1.53,-3.));
#916=VERTEX_POINT('',#915);
#917=EDGE_CURVE('E748',#916,#916,#914,.T.);
#918=ORIENTED_EDGE('',*,*,#917,.F.);
#919=EDGE_LOOP('',(#918));
#920=FACE_BOUND('',#919,.T.);
#921=ORIENTED_EDGE('',*,*,#900,.T.);
#922=EDGE_LOOP('',(#921));
#923=FACE_BOUND('',#922,.T.);
#924=ADVANCED_FACE('F768',(#920,#923),#909,.T.);
#925=CARTESIAN_POINT('',(0.,0.,0.));
#926=DIRECTION('',(0.,-1.,0.));
#927=DIRECTION('',(0.,0.,-1.));
#928=AXIS2_PLACEMENT_3D('',#925,#926,#927);
#929=CYLINDRICAL_SURFACE('',#928,2.5);
#930=CARTESIAN_POINT('',(0.,2.94748626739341,0.));
#931=DIRECTION('',(0.,-1.,0.));
#932=DIRECTION('',(0.,0.,-1.));
#933=AXIS2_PLACEMENT_3D('',#930,#931,#932);
#934=CIRCLE('',#933,2.5);
#935=CARTESIAN_POINT('',(0.,2.94748626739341,-2.5));
#936=VERTEX_POINT('',#935);
#937=EDGE_CURVE('E728',#936,#936,#934,.T.);
#938=ORIENTED_EDGE('',*,*,#937,.F.);
#939=EDGE_LOOP('',(#938));
#940=FACE_BOUND('',#939,.T.);
#941=CARTESIAN_POINT('',(0.,-1.17748626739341,0.));
#942=DIRECTION('',(0.,-1.,0.));
#943=DIRECTION('',(0.,0.,-1.));
#944=AXIS2_PLACEMENT_3D('',#941,#942,#943);
#945=CIRCLE('',#944,2.5);
#946=CARTESIAN_POINT('',(0.,-1.17748626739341,-2.5));
#947=VERTEX_POINT('',#946);
#948=EDGE_CURVE('E739',#947,#947,#945,.T.);
#949=ORIENTED_EDGE('',*,*,#948,.T.);
#950=EDGE_LOOP('',(#949));
#951=FACE_BOUND('',#950,.T.);
#952=ADVANCED_FACE('F775',(#940,#951),#929,.F.);
#953=CARTESIAN_POINT('',(3.45963274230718,3.3,0.));
#954=DIRECTION('',(0.,1.,0.));
#955=DIRECTION('',(0.,0.,1.));
#956=AXIS2_PLACEMENT_3D('',#953,#954,#955);
#957=PLANE('',#956);
#958=CARTESIAN_POINT('',(0.,3.3,0.));
#959=DIRECTION('',(0.,1.,0.));
#960=DIRECTION('',(0.,0.,1.));
#961=AXIS2_PLACEMENT_3D('',#958,#959,#960);
#962=CIRCLE('',#961,3.);
#963=CARTESIAN_POINT('',(0.,3.3,3.));
#964=VERTEX_POINT('',#963);
#965=EDGE_CURVE('E45',#964,#964,#962,.T.);
#966=ORIENTED_EDGE('',*,*,#965,.F.);
#967=EDGE_LOOP('',(#966));
#968=FACE_BOUND('',#967,.T.);
#969=CARTESIAN_POINT('',(0.,3.3,0.));
#970=DIRECTION('',(0.,-1.,0.));
#971=DIRECTION('',(0.,0.,-1.));
#972=AXIS2_PLACEMENT_3D('',#969,#970,#971);
#973=CIRCLE('',#972,3.45963274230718);
#974=CARTESIAN_POINT('',(0.,3.3,-3.45963274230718));
#975=VERTEX_POINT('',#974);
#976=EDGE_CURVE('E749',#975,#975,#973,.T.);
#977=ORIENTED_EDGE('',*,*,#976,.F.);
#978=EDGE_LOOP('',(#977));
#979=FACE_BOUND('',#978,.T.);
#980=ADVANCED_FACE('F800',(#968,#979),#957,.T.);
#981=CARTESIAN_POINT('',(0.,2.2,0.));
#982=DIRECTION('',(0.,-1.,0.));
#983=DIRECTION('',(0.,0.,-1.));
#984=AXIS2_PLACEMENT_3D('',#981,#982,#983);
#985=CONICAL_SURFACE('',#984,3.86,0.349065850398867);
#986=ORIENTED_EDGE('',*,*,#976,.T.);
#987=EDGE_LOOP('',(#986));
#988=FACE_BOUND('',#987,.T.);
#989=ORIENTED_EDGE('',*,*,#31,.F.);
#990=EDGE_LOOP('',(#989));
#991=FACE_BOUND('',#990,.T.);
#992=ADVANCED_FACE('F798',(#988,#991),#985,.T.);
#993=CARTESIAN_POINT('',(0.,-2.54,0.));
#994=DIRECTION('',(0.,-1.,0.));
#995=DIRECTION('',(0.,0.,-1.));
#996=AXIS2_PLACEMENT_3D('',#993,#994,#995);
#997=CYLINDRICAL_SURFACE('',#996,3.);
#998=ORIENTED_EDGE('',*,*,#917,.T.);
#999=EDGE_LOOP('',(#998));
#1000=FACE_BOUND('',#999,.T.);
#1001=CARTESIAN_POINT('',(0.,-1.52746,0.));
#1002=DIRECTION('',(0.,-1.,0.));
#1003=DIRECTION('',(0.,0.,-1.));
#1004=AXIS2_PLACEMENT_3D('',#1001,#1002,#1003);
#1005=CIRCLE('',#1004,3.);
#1006=CARTESIAN_POINT('',(0.,-1.52746,-3.));
#1007=VERTEX_POINT('',#1006);
#1008=EDGE_CURVE('E745',#1007,#1007,#1005,.T.);
#1009=ORIENTED_EDGE('',*,*,#1008,.F.);
#1010=EDGE_LOOP('',(#1009));
#1011=FACE_BOUND('',#1010,.T.);
#1012=ADVANCED_FACE('F766',(#1000,#1011),#997,.F.);
#1013=CARTESIAN_POINT('',(0.,-1.52746,0.));
#1014=DIRECTION('',(0.,-1.,0.));
#1015=DIRECTION('',(0.,0.,-1.));
#1016=AXIS2_PLACEMENT_3D('',#1013,#1014,#1015);
#1017=CONICAL_SURFACE('',#1016,3.,0.960105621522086);
#1018=ORIENTED_EDGE('',*,*,#948,.F.);
#1019=EDGE_LOOP('',(#1018));
#1020=FACE_BOUND('',#1019,.T.);
#1021=ORIENTED_EDGE('',*,*,#1008,.T.);
#1022=EDGE_LOOP('',(#1021));
#1023=FACE_BOUND('',#1022,.T.);
#1024=ADVANCED_FACE('F809',(#1020,#1023),#1017,.F.);
#1025=CARTESIAN_POINT('',(0.,2.94748626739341,0.));
#1026=DIRECTION('',(0.,1.,0.));
#1027=DIRECTION('',(0.,0.,1.));
#1028=AXIS2_PLACEMENT_3D('',#1025,#1026,#1027);
#1029=CONICAL_SURFACE('',#1028,2.5,0.960105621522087);
#1030=CARTESIAN_POINT('',(0.,3.29746,0.));
#1031=DIRECTION('',(0.,-1.,0.));
#1032=DIRECTION('',(0.,0.,-1.));
#1033=AXIS2_PLACEMENT_3D('',#1030,#1031,#1032);
#1034=CIRCLE('',#1033,3.);
#1035=CARTESIAN_POINT('',(0.,3.29746,-3.));
#1036=VERTEX_POINT('',#1035);
#1037=EDGE_CURVE('E740',#1036,#1036,#1034,.T.);
#1038=ORIENTED_EDGE('',*,*,#1037,.F.);
#1039=EDGE_LOOP('',(#1038));
#1040=FACE_BOUND('',#1039,.T.);
#1041=ORIENTED_EDGE('',*,*,#937,.T.);
#1042=EDGE_LOOP('',(#1041));
#1043=FACE_BOUND('',#1042,.T.);
#1044=ADVANCED_FACE('F823',(#1040,#1043),#1029,.F.);
#1045=CARTESIAN_POINT('',(0.,-2.54,0.));
#1046=DIRECTION('',(0.,-1.,0.));
#1047=DIRECTION('',(0.,0.,-1.));
#1048=AXIS2_PLACEMENT_3D('',#1045,#1046,#1047);
#1049=CYLINDRICAL_SURFACE('',#1048,3.);
#1050=ORIENTED_EDGE('',*,*,#965,.T.);
#1051=EDGE_LOOP('',(#1050));
#1052=FACE_BOUND('',#1051,.T.);
#1053=ORIENTED_EDGE('',*,*,#1037,.T.);
#1054=EDGE_LOOP('',(#1053));
#1055=FACE_BOUND('',#1054,.T.);
#1056=ADVANCED_FACE('F828',(#1052,#1055),#1049,.F.);
#1057=CARTESIAN_POINT('',(0.635662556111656,0.,4.82833647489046));
#1058=DIRECTION('',(0.573784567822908,0.,-0.819006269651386));
#1059=DIRECTION('',(-0.819006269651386,0.,-0.573784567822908));
#1060=AXIS2_PLACEMENT_3D('',#1057,#1058,#1059);
#1061=PLANE('',#1060);
#1062=ORIENTED_EDGE('',*,*,#823,.T.);
#1063=DIRECTION('',(0.,-1.,0.));
#1064=VECTOR('',#1063,1.);
#1065=CARTESIAN_POINT('',(0.635662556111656,0.,4.82833647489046));
#1066=LINE('',#1065,#1064);
#1067=EDGE_CURVE('E726',#75,#814,#1066,.T.);
#1068=ORIENTED_EDGE('',*,*,#1067,.F.);
#1069=ORIENTED_EDGE('',*,*,#76,.F.);
#1070=DIRECTION('',(0.,-1.,0.));
#1071=VECTOR('',#1070,1.);
#1072=CARTESIAN_POINT('',(0.,0.,4.383));
#1073=LINE('',#1072,#1071);
#1074=EDGE_CURVE('E731',#67,#822,#1073,.T.);
#1075=ORIENTED_EDGE('',*,*,#1074,.T.);
#1076=EDGE_LOOP('',(#1062,#1068,#1069,#1075));
#1077=FACE_BOUND('',#1076,.T.);
#1078=ADVANCED_FACE('F833',(#1077),#1061,.F.);
#1079=CARTESIAN_POINT('',(0.,0.,4.383));
#1080=DIRECTION('',(-0.573784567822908,0.,-0.819006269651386));
#1081=DIRECTION('',(-0.819006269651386,0.,0.573784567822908));
#1082=AXIS2_PLACEMENT_3D('',#1079,#1080,#1081);
#1083=PLANE('',#1082);
#1084=ORIENTED_EDGE('',*,*,#829,.T.);
#1085=ORIENTED_EDGE('',*,*,#1074,.F.);
#1086=ORIENTED_EDGE('',*,*,#68,.F.);
#1087=DIRECTION('',(0.,-1.,0.));
#1088=VECTOR('',#1087,1.);
#1089=CARTESIAN_POINT('',(-0.635662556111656,0.,4.82833647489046));
#1090=LINE('',#1089,#1088);
#1091=EDGE_CURVE('E352',#59,#454,#1090,.T.);
#1092=ORIENTED_EDGE('',*,*,#1091,.T.);
#1093=EDGE_LOOP('',(#1084,#1085,#1086,#1092));
#1094=FACE_BOUND('',#1093,.T.);
#1095=ADVANCED_FACE('F837',(#1094),#1083,.F.);
#1096=CARTESIAN_POINT('',(1.86366831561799,0.,4.49929332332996));
#1097=DIRECTION('',(0.342258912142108,0.,-0.93960568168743));
#1098=DIRECTION('',(-0.939605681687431,0.,-0.342258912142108));
#1099=AXIS2_PLACEMENT_3D('',#1096,#1097,#1098);
#1100=PLANE('',#1099);
#1101=ORIENTED_EDGE('',*,*,#807,.T.);
#1102=DIRECTION('',(0.,-1.,0.));
#1103=VECTOR('',#1102,1.);
#1104=CARTESIAN_POINT('',(1.86366831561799,0.,4.49929332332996));
#1105=LINE('',#1104,#1103);
#1106=EDGE_CURVE('E713',#91,#798,#1105,.T.);
#1107=ORIENTED_EDGE('',*,*,#1106,.F.);
#1108=ORIENTED_EDGE('',*,*,#92,.F.);
#1109=DIRECTION('',(0.,-1.,0.));
#1110=VECTOR('',#1109,1.);
#1111=CARTESIAN_POINT('',(1.13440387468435,0.,4.23365289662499));
#1112=LINE('',#1111,#1110);
#1113=EDGE_CURVE('E706',#83,#806,#1112,.T.);
#1114=ORIENTED_EDGE('',*,*,#1113,.T.);
#1115=EDGE_LOOP('',(#1101,#1107,#1108,#1114));
#1116=FACE_BOUND('',#1115,.T.);
#1117=ADVANCED_FACE('F836',(#1116),#1100,.F.);
#1118=CARTESIAN_POINT('',(1.13440387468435,0.,4.23365289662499));
#1119=DIRECTION('',(-0.766207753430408,0.,-0.642592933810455));
#1120=DIRECTION('',(-0.642592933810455,0.,0.766207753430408));
#1121=AXIS2_PLACEMENT_3D('',#1118,#1119,#1120);
#1122=PLANE('',#1121);
#1123=ORIENTED_EDGE('',*,*,#815,.T.);
#1124=ORIENTED_EDGE('',*,*,#1113,.F.);
#1125=ORIENTED_EDGE('',*,*,#84,.F.);
#1126=ORIENTED_EDGE('',*,*,#1067,.T.);
#1127=EDGE_LOOP('',(#1123,#1124,#1125,#1126));
#1128=FACE_BOUND('',#1127,.T.);
#1129=ADVANCED_FACE('F843',(#1128),#1122,.F.);
#1130=CARTESIAN_POINT('',(2.96466815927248,0.,3.86363076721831));
#1131=DIRECTION('',(0.087408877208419,0.,-0.996172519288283));
#1132=DIRECTION('',(-0.996172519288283,0.,-0.087408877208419));
#1133=AXIS2_PLACEMENT_3D('',#1130,#1131,#1132);
#1134=PLANE('',#1133);
#1135=ORIENTED_EDGE('',*,*,#791,.T.);
#1136=DIRECTION('',(0.,-1.,0.));
#1137=VECTOR('',#1136,1.);
#1138=CARTESIAN_POINT('',(2.96466815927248,0.,3.86363076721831));
#1139=LINE('',#1138,#1137);
#1140=EDGE_CURVE('E695',#107,#782,#1139,.T.);
#1141=ORIENTED_EDGE('',*,*,#1140,.F.);
#1142=ORIENTED_EDGE('',*,*,#108,.F.);
#1143=DIRECTION('',(0.,-1.,0.));
#1144=VECTOR('',#1143,1.);
#1145=CARTESIAN_POINT('',(2.1915,0.,3.79578934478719));
#1146=LINE('',#1145,#1144);
#1147=EDGE_CURVE('E686',#99,#790,#1146,.T.);
#1148=ORIENTED_EDGE('',*,*,#1147,.T.);
#1149=EDGE_LOOP('',(#1135,#1141,#1142,#1148));
#1150=FACE_BOUND('',#1149,.T.);
#1151=ADVANCED_FACE('F850',(#1150),#1134,.F.);
#1152=CARTESIAN_POINT('',(2.1915,0.,3.79578934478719));
#1153=DIRECTION('',(-0.906415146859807,0.,-0.422387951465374));
#1154=DIRECTION('',(-0.422387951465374,0.,0.906415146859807));
#1155=AXIS2_PLACEMENT_3D('',#1152,#1153,#1154);
#1156=PLANE('',#1155);
#1157=ORIENTED_EDGE('',*,*,#799,.T.);
#1158=ORIENTED_EDGE('',*,*,#1147,.F.);
#1159=ORIENTED_EDGE('',*,*,#100,.F.);
#1160=ORIENTED_EDGE('',*,*,#1106,.T.);
#1161=EDGE_LOOP('',(#1157,#1158,#1159,#1160));
#1162=FACE_BOUND('',#1161,.T.);
#1163=ADVANCED_FACE('F855',(#1162),#1156,.F.);
#1164=CARTESIAN_POINT('',(3.86363076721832,0.,2.96466815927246));
#1165=DIRECTION('',(-0.173397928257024,0.,-0.984851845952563));
#1166=DIRECTION('',(-0.984851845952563,0.,0.173397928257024));
#1167=AXIS2_PLACEMENT_3D('',#1164,#1165,#1166);
#1168=PLANE('',#1167);
#1169=ORIENTED_EDGE('',*,*,#775,.T.);
#1170=DIRECTION('',(0.,-1.,0.));
#1171=VECTOR('',#1170,1.);
#1172=CARTESIAN_POINT('',(3.86363076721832,0.,2.96466815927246));
#1173=LINE('',#1172,#1171);
#1174=EDGE_CURVE('E685',#123,#766,#1173,.T.);
#1175=ORIENTED_EDGE('',*,*,#1174,.F.);
#1176=ORIENTED_EDGE('',*,*,#124,.F.);
#1177=DIRECTION('',(0.,-1.,0.));
#1178=VECTOR('',#1177,1.);
#1179=CARTESIAN_POINT('',(3.09924902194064,0.,3.09924902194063));
#1180=LINE('',#1179,#1178);
#1181=EDGE_CURVE('E678',#115,#774,#1180,.T.);
#1182=ORIENTED_EDGE('',*,*,#1181,.T.);
#1183=EDGE_LOOP('',(#1169,#1175,#1176,#1182));
#1184=FACE_BOUND('',#1183,.T.);
#1185=ADVANCED_FACE('F860',(#1184),#1168,.F.);
#1186=CARTESIAN_POINT('',(3.09924902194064,0.,3.09924902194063));
#1187=DIRECTION('',(-0.984851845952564,0.,-0.173397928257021));
#1188=DIRECTION('',(-0.173397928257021,0.,0.984851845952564));
#1189=AXIS2_PLACEMENT_3D('',#1186,#1187,#1188);
#1190=PLANE('',#1189);
#1191=ORIENTED_EDGE('',*,*,#783,.T.);
#1192=ORIENTED_EDGE('',*,*,#1181,.F.);
#1193=ORIENTED_EDGE('',*,*,#116,.F.);
#1194=ORIENTED_EDGE('',*,*,#1140,.T.);
#1195=EDGE_LOOP('',(#1191,#1192,#1193,#1194));
#1196=FACE_BOUND('',#1195,.T.);
#1197=ADVANCED_FACE('F859',(#1196),#1190,.F.);
#1198=CARTESIAN_POINT('',(4.49929332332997,0.,1.86366831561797));
#1199=DIRECTION('',(-0.422387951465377,0.,-0.906415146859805));
#1200=DIRECTION('',(-0.906415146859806,0.,0.422387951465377));
#1201=AXIS2_PLACEMENT_3D('',#1198,#1199,#1200);
#1202=PLANE('',#1201);
#1203=ORIENTED_EDGE('',*,*,#759,.T.);
#1204=DIRECTION('',(0.,-1.,0.));
#1205=VECTOR('',#1204,1.);
#1206=CARTESIAN_POINT('',(4.49929332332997,0.,1.86366831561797));
#1207=LINE('',#1206,#1205);
#1208=EDGE_CURVE('E669',#139,#750,#1207,.T.);
#1209=ORIENTED_EDGE('',*,*,#1208,.F.);
#1210=ORIENTED_EDGE('',*,*,#140,.F.);
#1211=DIRECTION('',(0.,-1.,0.));
#1212=VECTOR('',#1211,1.);
#1213=CARTESIAN_POINT('',(3.7957893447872,0.,2.19149999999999));
#1214=LINE('',#1213,#1212);
#1215=EDGE_CURVE('E661',#131,#758,#1214,.T.);
#1216=ORIENTED_EDGE('',*,*,#1215,.T.);
#1217=EDGE_LOOP('',(#1203,#1209,#1210,#1216));
#1218=FACE_BOUND('',#1217,.T.);
#1219=ADVANCED_FACE('F862',(#1218),#1202,.F.);
#1220=CARTESIAN_POINT('',(3.7957893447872,0.,2.19149999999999));
#1221=DIRECTION('',(-0.996172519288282,0.,0.0874088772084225));
#1222=DIRECTION('',(0.0874088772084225,0.,0.996172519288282));
#1223=AXIS2_PLACEMENT_3D('',#1220,#1221,#1222);
#1224=PLANE('',#1223);
#1225=ORIENTED_EDGE('',*,*,#767,.T.);
#1226=ORIENTED_EDGE('',*,*,#1215,.F.);
#1227=ORIENTED_EDGE('',*,*,#132,.F.);
#1228=ORIENTED_EDGE('',*,*,#1174,.T.);
#1229=EDGE_LOOP('',(#1225,#1226,#1227,#1228));
#1230=FACE_BOUND('',#1229,.T.);
#1231=ADVANCED_FACE('F870',(#1230),#1224,.F.);
#1232=CARTESIAN_POINT('',(4.82833647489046,0.,0.635662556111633));
#1233=DIRECTION('',(-0.642592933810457,0.,-0.766207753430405));
#1234=DIRECTION('',(-0.766207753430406,0.,0.642592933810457));
#1235=AXIS2_PLACEMENT_3D('',#1232,#1233,#1234);
#1236=PLANE('',#1235);
#1237=ORIENTED_EDGE('',*,*,#743,.T.);
#1238=DIRECTION('',(0.,-1.,0.));
#1239=VECTOR('',#1238,1.);
#1240=CARTESIAN_POINT('',(4.82833647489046,0.,0.635662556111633));
#1241=LINE('',#1240,#1239);
#1242=EDGE_CURVE('E655',#155,#734,#1241,.T.);
#1243=ORIENTED_EDGE('',*,*,#1242,.F.);
#1244=ORIENTED_EDGE('',*,*,#156,.F.);
#1245=DIRECTION('',(0.,-1.,0.));
#1246=VECTOR('',#1245,1.);
#1247=CARTESIAN_POINT('',(4.23365289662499,0.,1.13440387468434));
#1248=LINE('',#1247,#1246);
#1249=EDGE_CURVE('E647',#147,#742,#1248,.T.);
#1250=ORIENTED_EDGE('',*,*,#1249,.T.);
#1251=EDGE_LOOP('',(#1237,#1243,#1244,#1250));
#1252=FACE_BOUND('',#1251,.T.);
#1253=ADVANCED_FACE('F869',(#1252),#1236,.F.);
#1254=CARTESIAN_POINT('',(4.23365289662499,0.,1.13440387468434));
#1255=DIRECTION('',(-0.939605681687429,0.,0.342258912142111));
#1256=DIRECTION('',(0.342258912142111,0.,0.939605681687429));
#1257=AXIS2_PLACEMENT_3D('',#1254,#1255,#1256);
#1258=PLANE('',#1257);
#1259=ORIENTED_EDGE('',*,*,#751,.T.);
#1260=ORIENTED_EDGE('',*,*,#1249,.F.);
#1261=ORIENTED_EDGE('',*,*,#148,.F.);
#1262=ORIENTED_EDGE('',*,*,#1208,.T.);
#1263=EDGE_LOOP('',(#1259,#1260,#1261,#1262));
#1264=FACE_BOUND('',#1263,.T.);
#1265=ADVANCED_FACE('F872',(#1264),#1258,.F.);
#1266=CARTESIAN_POINT('',(4.82833647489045,0.,-0.635662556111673));
#1267=DIRECTION('',(-0.819006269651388,0.,-0.573784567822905));
#1268=DIRECTION('',(-0.573784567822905,0.,0.819006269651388));
#1269=AXIS2_PLACEMENT_3D('',#1266,#1267,#1268);
#1270=PLANE('',#1269);
#1271=ORIENTED_EDGE('',*,*,#727,.T.);
#1272=DIRECTION('',(0.,-1.,0.));
#1273=VECTOR('',#1272,1.);
#1274=CARTESIAN_POINT('',(4.82833647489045,0.,-0.635662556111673));
#1275=LINE('',#1274,#1273);
#1276=EDGE_CURVE('E636',#171,#718,#1275,.T.);
#1277=ORIENTED_EDGE('',*,*,#1276,.F.);
#1278=ORIENTED_EDGE('',*,*,#172,.F.);
#1279=DIRECTION('',(0.,-1.,0.));
#1280=VECTOR('',#1279,1.);
#1281=CARTESIAN_POINT('',(4.383,0.,0.));
#1282=LINE('',#1281,#1280);
#1283=EDGE_CURVE('E631',#163,#726,#1282,.T.);
#1284=ORIENTED_EDGE('',*,*,#1283,.T.);
#1285=EDGE_LOOP('',(#1271,#1277,#1278,#1284));
#1286=FACE_BOUND('',#1285,.T.);
#1287=ADVANCED_FACE('F876',(#1286),#1270,.F.);
#1288=CARTESIAN_POINT('',(4.383,0.,0.));
#1289=DIRECTION('',(-0.819006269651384,0.,0.573784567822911));
#1290=DIRECTION('',(0.573784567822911,0.,0.819006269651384));
#1291=AXIS2_PLACEMENT_3D('',#1288,#1289,#1290);
#1292=PLANE('',#1291);
#1293=ORIENTED_EDGE('',*,*,#735,.T.);
#1294=ORIENTED_EDGE('',*,*,#1283,.F.);
#1295=ORIENTED_EDGE('',*,*,#164,.F.);
#1296=ORIENTED_EDGE('',*,*,#1242,.T.);
#1297=EDGE_LOOP('',(#1293,#1294,#1295,#1296));
#1298=FACE_BOUND('',#1297,.T.);
#1299=ADVANCED_FACE('F881',(#1298),#1292,.F.);
#1300=CARTESIAN_POINT('',(4.49929332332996,0.,-1.86366831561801));
#1301=DIRECTION('',(-0.939605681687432,0.,-0.342258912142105));
#1302=DIRECTION('',(-0.342258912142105,0.,0.939605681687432));
#1303=AXIS2_PLACEMENT_3D('',#1300,#1301,#1302);
#1304=PLANE('',#1303);
#1305=ORIENTED_EDGE('',*,*,#711,.T.);
#1306=DIRECTION('',(0.,-1.,0.));
#1307=VECTOR('',#1306,1.);
#1308=CARTESIAN_POINT('',(4.49929332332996,0.,-1.86366831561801));
#1309=LINE('',#1308,#1307);
#1310=EDGE_CURVE('E619',#187,#702,#1309,.T.);
#1311=ORIENTED_EDGE('',*,*,#1310,.F.);
#1312=ORIENTED_EDGE('',*,*,#188,.F.);
#1313=DIRECTION('',(0.,-1.,0.));
#1314=VECTOR('',#1313,1.);
#1315=CARTESIAN_POINT('',(4.23365289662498,0.,-1.13440387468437));
#1316=LINE('',#1315,#1314);
#1317=EDGE_CURVE('E612',#179,#710,#1316,.T.);
#1318=ORIENTED_EDGE('',*,*,#1317,.T.);
#1319=EDGE_LOOP('',(#1305,#1311,#1312,#1318));
#1320=FACE_BOUND('',#1319,.T.);
#1321=ADVANCED_FACE('F886',(#1320),#1304,.F.);
#1322=CARTESIAN_POINT('',(4.23365289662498,0.,-1.13440387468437));
#1323=DIRECTION('',(-0.642592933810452,0.,0.76620775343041));
#1324=DIRECTION('',(0.76620775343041,0.,0.642592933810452));
#1325=AXIS2_PLACEMENT_3D('',#1322,#1323,#1324);
#1326=PLANE('',#1325);
#1327=ORIENTED_EDGE('',*,*,#719,.T.);
#1328=ORIENTED_EDGE('',*,*,#1317,.F.);
#1329=ORIENTED_EDGE('',*,*,#180,.F.);
#1330=ORIENTED_EDGE('',*,*,#1276,.T.);
#1331=EDGE_LOOP('',(#1327,#1328,#1329,#1330));
#1332=FACE_BOUND('',#1331,.T.);
#1333=ADVANCED_FACE('F891',(#1332),#1326,.F.);
#1334=CARTESIAN_POINT('',(3.8636307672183,0.,-2.96466815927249));
#1335=DIRECTION('',(-0.996172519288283,0.,-0.0874088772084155));
#1336=DIRECTION('',(-0.0874088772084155,0.,0.996172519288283));
#1337=AXIS2_PLACEMENT_3D('',#1334,#1335,#1336);
#1338=PLANE('',#1337);
#1339=ORIENTED_EDGE('',*,*,#695,.T.);
#1340=DIRECTION('',(0.,-1.,0.));
#1341=VECTOR('',#1340,1.);
#1342=CARTESIAN_POINT('',(3.8636307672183,0.,-2.96466815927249));
#1343=LINE('',#1342,#1341);
#1344=EDGE_CURVE('E603',#203,#686,#1343,.T.);
#1345=ORIENTED_EDGE('',*,*,#1344,.F.);
#1346=ORIENTED_EDGE('',*,*,#204,.F.);
#1347=DIRECTION('',(0.,-1.,0.));
#1348=VECTOR('',#1347,1.);
#1349=CARTESIAN_POINT('',(3.79578934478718,0.,-2.19150000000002));
#1350=LINE('',#1349,#1348);
#1351=EDGE_CURVE('E599',#195,#694,#1350,.T.);
#1352=ORIENTED_EDGE('',*,*,#1351,.T.);
#1353=EDGE_LOOP('',(#1339,#1345,#1346,#1352));
#1354=FACE_BOUND('',#1353,.T.);
#1355=ADVANCED_FACE('F892',(#1354),#1338,.F.);
#1356=CARTESIAN_POINT('',(3.79578934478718,0.,-2.19150000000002));
#1357=DIRECTION('',(-0.42238795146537,0.,0.906415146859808));
#1358=DIRECTION('',(0.906415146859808,0.,0.42238795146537));
#1359=AXIS2_PLACEMENT_3D('',#1356,#1357,#1358);
#1360=PLANE('',#1359);
#1361=ORIENTED_EDGE('',*,*,#703,.T.);
#1362=ORIENTED_EDGE('',*,*,#1351,.F.);
#1363=ORIENTED_EDGE('',*,*,#196,.F.);
#1364=ORIENTED_EDGE('',*,*,#1310,.T.);
#1365=EDGE_LOOP('',(#1361,#1362,#1363,#1364));
#1366=FACE_BOUND('',#1365,.T.);
#1367=ADVANCED_FACE('F898',(#1366),#1360,.F.);
#1368=CARTESIAN_POINT('',(2.96466815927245,0.,-3.86363076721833));
#1369=DIRECTION('',(-0.984851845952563,0.,0.173397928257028));
#1370=DIRECTION('',(0.173397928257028,0.,0.984851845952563));
#1371=AXIS2_PLACEMENT_3D('',#1368,#1369,#1370);
#1372=PLANE('',#1371);
#1373=ORIENTED_EDGE('',*,*,#679,.T.);
#1374=DIRECTION('',(0.,-1.,0.));
#1375=VECTOR('',#1374,1.);
#1376=CARTESIAN_POINT('',(2.96466815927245,0.,-3.86363076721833));
#1377=LINE('',#1376,#1375);
#1378=EDGE_CURVE('E587',#219,#670,#1377,.T.);
#1379=ORIENTED_EDGE('',*,*,#1378,.F.);
#1380=ORIENTED_EDGE('',*,*,#220,.F.);
#1381=DIRECTION('',(0.,-1.,0.));
#1382=VECTOR('',#1381,1.);
#1383=CARTESIAN_POINT('',(3.09924902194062,0.,-3.09924902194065));
#1384=LINE('',#1383,#1382);
#1385=EDGE_CURVE('E584',#211,#678,#1384,.T.);
#1386=ORIENTED_EDGE('',*,*,#1385,.T.);
#1387=EDGE_LOOP('',(#1373,#1379,#1380,#1386));
#1388=FACE_BOUND('',#1387,.T.);
#1389=ADVANCED_FACE('F905',(#1388),#1372,.F.);
#1390=CARTESIAN_POINT('',(3.09924902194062,0.,-3.09924902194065));
#1391=DIRECTION('',(-0.173397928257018,0.,0.984851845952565));
#1392=DIRECTION('',(0.984851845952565,0.,0.173397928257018));
#1393=AXIS2_PLACEMENT_3D('',#1390,#1391,#1392);
#1394=PLANE('',#1393);
#1395=ORIENTED_EDGE('',*,*,#687,.T.);
#1396=ORIENTED_EDGE('',*,*,#1385,.F.);
#1397=ORIENTED_EDGE('',*,*,#212,.F.);
#1398=ORIENTED_EDGE('',*,*,#1344,.T.);
#1399=EDGE_LOOP('',(#1395,#1396,#1397,#1398));
#1400=FACE_BOUND('',#1399,.T.);
#1401=ADVANCED_FACE('F907',(#1400),#1394,.F.);
#1402=CARTESIAN_POINT('',(1.86366831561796,0.,-4.49929332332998));
#1403=DIRECTION('',(-0.906415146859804,0.,0.42238795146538));
#1404=DIRECTION('',(0.42238795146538,0.,0.906415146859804));
#1405=AXIS2_PLACEMENT_3D('',#1402,#1403,#1404);
#1406=PLANE('',#1405);
#1407=ORIENTED_EDGE('',*,*,#663,.T.);
#1408=DIRECTION('',(0.,-1.,0.));
#1409=VECTOR('',#1408,1.);
#1410=CARTESIAN_POINT('',(1.86366831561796,0.,-4.49929332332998));
#1411=LINE('',#1410,#1409);
#1412=EDGE_CURVE('E575',#235,#654,#1411,.T.);
#1413=ORIENTED_EDGE('',*,*,#1412,.F.);
#1414=ORIENTED_EDGE('',*,*,#236,.F.);
#1415=DIRECTION('',(0.,-1.,0.));
#1416=VECTOR('',#1415,1.);
#1417=CARTESIAN_POINT('',(2.19149999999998,0.,-3.79578934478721));
#1418=LINE('',#1417,#1416);
#1419=EDGE_CURVE('E570',#227,#662,#1418,.T.);
#1420=ORIENTED_EDGE('',*,*,#1419,.T.);
#1421=EDGE_LOOP('',(#1407,#1413,#1414,#1420));
#1422=FACE_BOUND('',#1421,.T.);
#1423=ADVANCED_FACE('F910',(#1422),#1406,.F.);
#1424=CARTESIAN_POINT('',(2.19149999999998,0.,-3.79578934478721));
#1425=DIRECTION('',(0.087408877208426,0.,0.996172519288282));
#1426=DIRECTION('',(0.996172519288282,0.,-0.0874088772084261));
#1427=AXIS2_PLACEMENT_3D('',#1424,#1425,#1426);
#1428=PLANE('',#1427);
#1429=ORIENTED_EDGE('',*,*,#671,.T.);
#1430=ORIENTED_EDGE('',*,*,#1419,.F.);
#1431=ORIENTED_EDGE('',*,*,#228,.F.);
#1432=ORIENTED_EDGE('',*,*,#1378,.T.);
#1433=EDGE_LOOP('',(#1429,#1430,#1431,#1432));
#1434=FACE_BOUND('',#1433,.T.);
#1435=ADVANCED_FACE('F914',(#1434),#1428,.F.);
#1436=CARTESIAN_POINT('',(0.635662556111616,0.,-4.82833647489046));
#1437=DIRECTION('',(-0.766207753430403,0.,0.64259293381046));
#1438=DIRECTION('',(0.64259293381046,0.,0.766207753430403));
#1439=AXIS2_PLACEMENT_3D('',#1436,#1437,#1438);
#1440=PLANE('',#1439);
#1441=ORIENTED_EDGE('',*,*,#647,.T.);
#1442=DIRECTION('',(0.,-1.,0.));
#1443=VECTOR('',#1442,1.);
#1444=CARTESIAN_POINT('',(0.635662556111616,0.,-4.82833647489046));
#1445=LINE('',#1444,#1443);
#1446=EDGE_CURVE('E558',#251,#638,#1445,.T.);
#1447=ORIENTED_EDGE('',*,*,#1446,.F.);
#1448=ORIENTED_EDGE('',*,*,#252,.F.);
#1449=DIRECTION('',(0.,-1.,0.));
#1450=VECTOR('',#1449,1.);
#1451=CARTESIAN_POINT('',(1.13440387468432,0.,-4.23365289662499));
#1452=LINE('',#1451,#1450);
#1453=EDGE_CURVE('E553',#243,#646,#1452,.T.);
#1454=ORIENTED_EDGE('',*,*,#1453,.T.);
#1455=EDGE_LOOP('',(#1441,#1447,#1448,#1454));
#1456=FACE_BOUND('',#1455,.T.);
#1457=ADVANCED_FACE('F920',(#1456),#1440,.F.);
#1458=CARTESIAN_POINT('',(1.13440387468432,0.,-4.23365289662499));
#1459=DIRECTION('',(0.342258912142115,0.,0.939605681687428));
#1460=DIRECTION('',(0.939605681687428,0.,-0.342258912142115));
#1461=AXIS2_PLACEMENT_3D('',#1458,#1459,#1460);
#1462=PLANE('',#1461);
#1463=ORIENTED_EDGE('',*,*,#655,.T.);
#1464=ORIENTED_EDGE('',*,*,#1453,.F.);
#1465=ORIENTED_EDGE('',*,*,#244,.F.);
#1466=ORIENTED_EDGE('',*,*,#1412,.T.);
#1467=EDGE_LOOP('',(#1463,#1464,#1465,#1466));
#1468=FACE_BOUND('',#1467,.T.);
#1469=ADVANCED_FACE('F921',(#1468),#1462,.F.);
#1470=CARTESIAN_POINT('',(-0.63566255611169,0.,-4.82833647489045));
#1471=DIRECTION('',(-0.573784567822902,0.,0.81900626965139));
#1472=DIRECTION('',(0.81900626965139,0.,0.573784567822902));
#1473=AXIS2_PLACEMENT_3D('',#1470,#1471,#1472);
#1474=PLANE('',#1473);
#1475=ORIENTED_EDGE('',*,*,#631,.T.);
#1476=DIRECTION('',(0.,-1.,0.));
#1477=VECTOR('',#1476,1.);
#1478=CARTESIAN_POINT('',(-0.63566255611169,0.,-4.82833647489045));
#1479=LINE('',#1478,#1477);
#1480=EDGE_CURVE('E540',#267,#622,#1479,.T.);
#1481=ORIENTED_EDGE('',*,*,#1480,.F.);
#1482=ORIENTED_EDGE('',*,*,#268,.F.);
#1483=DIRECTION('',(0.,-1.,0.));
#1484=VECTOR('',#1483,1.);
#1485=CARTESIAN_POINT('',(0.,0.,-4.383));
#1486=LINE('',#1485,#1484);
#1487=EDGE_CURVE('E533',#259,#630,#1486,.T.);
#1488=ORIENTED_EDGE('',*,*,#1487,.T.);
#1489=EDGE_LOOP('',(#1475,#1481,#1482,#1488));
#1490=FACE_BOUND('',#1489,.T.);
#1491=ADVANCED_FACE('F926',(#1490),#1474,.F.);
#1492=CARTESIAN_POINT('',(0.,0.,-4.383));
#1493=DIRECTION('',(0.573784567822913,0.,0.819006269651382));
#1494=DIRECTION('',(0.819006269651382,0.,-0.573784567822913));
#1495=AXIS2_PLACEMENT_3D('',#1492,#1493,#1494);
#1496=PLANE('',#1495);
#1497=ORIENTED_EDGE('',*,*,#639,.T.);
#1498=ORIENTED_EDGE('',*,*,#1487,.F.);
#1499=ORIENTED_EDGE('',*,*,#260,.F.);
#1500=ORIENTED_EDGE('',*,*,#1446,.T.);
#1501=EDGE_LOOP('',(#1497,#1498,#1499,#1500));
#1502=FACE_BOUND('',#1501,.T.);
#1503=ADVANCED_FACE('F931',(#1502),#1496,.F.);
#1504=CARTESIAN_POINT('',(-1.86366831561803,0.,-4.49929332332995));
#1505=DIRECTION('',(-0.342258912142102,0.,0.939605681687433));
#1506=DIRECTION('',(0.939605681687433,0.,0.342258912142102));
#1507=AXIS2_PLACEMENT_3D('',#1504,#1505,#1506);
#1508=PLANE('',#1507);
#1509=ORIENTED_EDGE('',*,*,#615,.T.);
#1510=DIRECTION('',(0.,-1.,0.));
#1511=VECTOR('',#1510,1.);
#1512=CARTESIAN_POINT('',(-1.86366831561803,0.,-4.49929332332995));
#1513=LINE('',#1512,#1511);
#1514=EDGE_CURVE('E523',#283,#606,#1513,.T.);
#1515=ORIENTED_EDGE('',*,*,#1514,.F.);
#1516=ORIENTED_EDGE('',*,*,#284,.F.);
#1517=DIRECTION('',(0.,-1.,0.));
#1518=VECTOR('',#1517,1.);
#1519=CARTESIAN_POINT('',(-1.13440387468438,0.,-4.23365289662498));
#1520=LINE('',#1519,#1518);
#1521=EDGE_CURVE('E518',#275,#614,#1520,.T.);
#1522=ORIENTED_EDGE('',*,*,#1521,.T.);
#1523=EDGE_LOOP('',(#1509,#1515,#1516,#1522));
#1524=FACE_BOUND('',#1523,.T.);
#1525=ADVANCED_FACE('F933',(#1524),#1508,.F.);
#1526=CARTESIAN_POINT('',(-1.13440387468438,0.,-4.23365289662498));
#1527=DIRECTION('',(0.766207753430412,0.,0.642592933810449));
#1528=DIRECTION('',(0.642592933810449,0.,-0.766207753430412));
#1529=AXIS2_PLACEMENT_3D('',#1526,#1527,#1528);
#1530=PLANE('',#1529);
#1531=ORIENTED_EDGE('',*,*,#623,.T.);
#1532=ORIENTED_EDGE('',*,*,#1521,.F.);
#1533=ORIENTED_EDGE('',*,*,#276,.F.);
#1534=ORIENTED_EDGE('',*,*,#1480,.T.);
#1535=EDGE_LOOP('',(#1531,#1532,#1533,#1534));
#1536=FACE_BOUND('',#1535,.T.);
#1537=ADVANCED_FACE('F938',(#1536),#1530,.F.);
#1538=CARTESIAN_POINT('',(-2.96466815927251,0.,-3.86363076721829));
#1539=DIRECTION('',(-0.087408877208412,0.,0.996172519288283));
#1540=DIRECTION('',(0.996172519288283,0.,0.087408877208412));
#1541=AXIS2_PLACEMENT_3D('',#1538,#1539,#1540);
#1542=PLANE('',#1541);
#1543=ORIENTED_EDGE('',*,*,#599,.T.);
#1544=DIRECTION('',(0.,-1.,0.));
#1545=VECTOR('',#1544,1.);
#1546=CARTESIAN_POINT('',(-2.96466815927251,0.,-3.86363076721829));
#1547=LINE('',#1546,#1545);
#1548=EDGE_CURVE('E507',#299,#590,#1547,.T.);
#1549=ORIENTED_EDGE('',*,*,#1548,.F.);
#1550=ORIENTED_EDGE('',*,*,#300,.F.);
#1551=DIRECTION('',(0.,-1.,0.));
#1552=VECTOR('',#1551,1.);
#1553=CARTESIAN_POINT('',(-2.19150000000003,0.,-3.79578934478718));
#1554=LINE('',#1553,#1552);
#1555=EDGE_CURVE('E503',#291,#598,#1554,.T.);
#1556=ORIENTED_EDGE('',*,*,#1555,.T.);
#1557=EDGE_LOOP('',(#1543,#1549,#1550,#1556));
#1558=FACE_BOUND('',#1557,.T.);
#1559=ADVANCED_FACE('F942',(#1558),#1542,.F.);
#1560=CARTESIAN_POINT('',(-2.19150000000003,0.,-3.79578934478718));
#1561=DIRECTION('',(0.90641514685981,0.,0.422387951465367));
#1562=DIRECTION('',(0.422387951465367,0.,-0.90641514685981));
#1563=AXIS2_PLACEMENT_3D('',#1560,#1561,#1562);
#1564=PLANE('',#1563);
#1565=ORIENTED_EDGE('',*,*,#607,.T.);
#1566=ORIENTED_EDGE('',*,*,#1555,.F.);
#1567=ORIENTED_EDGE('',*,*,#292,.F.);
#1568=ORIENTED_EDGE('',*,*,#1514,.T.);
#1569=EDGE_LOOP('',(#1565,#1566,#1567,#1568));
#1570=FACE_BOUND('',#1569,.T.);
#1571=ADVANCED_FACE('F950',(#1570),#1564,.F.);
#1572=CARTESIAN_POINT('',(-3.86363076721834,0.,-2.96466815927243));
#1573=DIRECTION('',(0.173397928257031,0.,0.984851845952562));
#1574=DIRECTION('',(0.984851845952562,0.,-0.173397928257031));
#1575=AXIS2_PLACEMENT_3D('',#1572,#1573,#1574);
#1576=PLANE('',#1575);
#1577=ORIENTED_EDGE('',*,*,#583,.T.);
#1578=DIRECTION('',(0.,-1.,0.));
#1579=VECTOR('',#1578,1.);
#1580=CARTESIAN_POINT('',(-3.86363076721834,0.,-2.96466815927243));
#1581=LINE('',#1580,#1579);
#1582=EDGE_CURVE('E495',#315,#574,#1581,.T.);
#1583=ORIENTED_EDGE('',*,*,#1582,.F.);
#1584=ORIENTED_EDGE('',*,*,#316,.F.);
#1585=DIRECTION('',(0.,-1.,0.));
#1586=VECTOR('',#1585,1.);
#1587=CARTESIAN_POINT('',(-3.09924902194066,0.,-3.09924902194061));
#1588=LINE('',#1587,#1586);
#1589=EDGE_CURVE('E487',#307,#582,#1588,.T.);
#1590=ORIENTED_EDGE('',*,*,#1589,.T.);
#1591=EDGE_LOOP('',(#1577,#1583,#1584,#1590));
#1592=FACE_BOUND('',#1591,.T.);
#1593=ADVANCED_FACE('F947',(#1592),#1576,.F.);
#1594=CARTESIAN_POINT('',(-3.09924902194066,0.,-3.09924902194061));
#1595=DIRECTION('',(0.984851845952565,0.,0.173397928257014));
#1596=DIRECTION('',(0.173397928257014,0.,-0.984851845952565));
#1597=AXIS2_PLACEMENT_3D('',#1594,#1595,#1596);
#1598=PLANE('',#1597);
#1599=ORIENTED_EDGE('',*,*,#591,.T.);
#1600=ORIENTED_EDGE('',*,*,#1589,.F.);
#1601=ORIENTED_EDGE('',*,*,#308,.F.);
#1602=ORIENTED_EDGE('',*,*,#1548,.T.);
#1603=EDGE_LOOP('',(#1599,#1600,#1601,#1602));
#1604=FACE_BOUND('',#1603,.T.);
#1605=ADVANCED_FACE('F954',(#1604),#1598,.F.);
#1606=CARTESIAN_POINT('',(-4.49929332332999,0.,-1.86366831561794));
#1607=DIRECTION('',(0.422387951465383,0.,0.906415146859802));
#1608=DIRECTION('',(0.906415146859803,0.,-0.422387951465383));
#1609=AXIS2_PLACEMENT_3D('',#1606,#1607,#1608);
#1610=PLANE('',#1609);
#1611=ORIENTED_EDGE('',*,*,#567,.T.);
#1612=DIRECTION('',(0.,-1.,0.));
#1613=VECTOR('',#1612,1.);
#1614=CARTESIAN_POINT('',(-4.49929332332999,0.,-1.86366831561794));
#1615=LINE('',#1614,#1613);
#1616=EDGE_CURVE('E476',#331,#558,#1615,.T.);
#1617=ORIENTED_EDGE('',*,*,#1616,.F.);
#1618=ORIENTED_EDGE('',*,*,#332,.F.);
#1619=DIRECTION('',(0.,-1.,0.));
#1620=VECTOR('',#1619,1.);
#1621=CARTESIAN_POINT('',(-3.79578934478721,0.,-2.19149999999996));
#1622=LINE('',#1621,#1620);
#1623=EDGE_CURVE('E471',#323,#566,#1622,.T.);
#1624=ORIENTED_EDGE('',*,*,#1623,.T.);
#1625=EDGE_LOOP('',(#1611,#1617,#1618,#1624));
#1626=FACE_BOUND('',#1625,.T.);
#1627=ADVANCED_FACE('F958',(#1626),#1610,.F.);
#1628=CARTESIAN_POINT('',(-3.79578934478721,0.,-2.19149999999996));
#1629=DIRECTION('',(0.996172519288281,0.,-0.0874088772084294));
#1630=DIRECTION('',(-0.0874088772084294,0.,-0.996172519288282));
#1631=AXIS2_PLACEMENT_3D('',#1628,#1629,#1630);
#1632=PLANE('',#1631);
#1633=ORIENTED_EDGE('',*,*,#575,.T.);
#1634=ORIENTED_EDGE('',*,*,#1623,.F.);
#1635=ORIENTED_EDGE('',*,*,#324,.F.);
#1636=ORIENTED_EDGE('',*,*,#1582,.T.);
#1637=EDGE_LOOP('',(#1633,#1634,#1635,#1636));
#1638=FACE_BOUND('',#1637,.T.);
#1639=ADVANCED_FACE('F962',(#1638),#1632,.F.);
#1640=CARTESIAN_POINT('',(-4.82833647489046,0.,-0.635662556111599));
#1641=DIRECTION('',(0.642592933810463,0.,0.766207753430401));
#1642=DIRECTION('',(0.766207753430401,0.,-0.642592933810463));
#1643=AXIS2_PLACEMENT_3D('',#1640,#1641,#1642);
#1644=PLANE('',#1643);
#1645=ORIENTED_EDGE('',*,*,#551,.T.);
#1646=DIRECTION('',(0.,-1.,0.));
#1647=VECTOR('',#1646,1.);
#1648=CARTESIAN_POINT('',(-4.82833647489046,0.,-0.635662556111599));
#1649=LINE('',#1648,#1647);
#1650=EDGE_CURVE('E459',#347,#542,#1649,.T.);
#1651=ORIENTED_EDGE('',*,*,#1650,.F.);
#1652=ORIENTED_EDGE('',*,*,#348,.F.);
#1653=DIRECTION('',(0.,-1.,0.));
#1654=VECTOR('',#1653,1.);
#1655=CARTESIAN_POINT('',(-4.233652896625,0.,-1.13440387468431));
#1656=LINE('',#1655,#1654);
#1657=EDGE_CURVE('E455',#339,#550,#1656,.T.);
#1658=ORIENTED_EDGE('',*,*,#1657,.T.);
#1659=EDGE_LOOP('',(#1645,#1651,#1652,#1658));
#1660=FACE_BOUND('',#1659,.T.);
#1661=ADVANCED_FACE('F967',(#1660),#1644,.F.);
#1662=CARTESIAN_POINT('',(-4.233652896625,0.,-1.13440387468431));
#1663=DIRECTION('',(0.939605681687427,0.,-0.342258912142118));
#1664=DIRECTION('',(-0.342258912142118,0.,-0.939605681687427));
#1665=AXIS2_PLACEMENT_3D('',#1662,#1663,#1664);
#1666=PLANE('',#1665);
#1667=ORIENTED_EDGE('',*,*,#559,.T.);
#1668=ORIENTED_EDGE('',*,*,#1657,.F.);
#1669=ORIENTED_EDGE('',*,*,#340,.F.);
#1670=ORIENTED_EDGE('',*,*,#1616,.T.);
#1671=EDGE_LOOP('',(#1667,#1668,#1669,#1670));
#1672=FACE_BOUND('',#1671,.T.);
#1673=ADVANCED_FACE('F971',(#1672),#1666,.F.);
#1674=CARTESIAN_POINT('',(-4.82833647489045,0.,0.635662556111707));
#1675=DIRECTION('',(0.819006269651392,0.,0.573784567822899));
#1676=DIRECTION('',(0.573784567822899,0.,-0.819006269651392));
#1677=AXIS2_PLACEMENT_3D('',#1674,#1675,#1676);
#1678=PLANE('',#1677);
#1679=ORIENTED_EDGE('',*,*,#535,.T.);
#1680=DIRECTION('',(0.,-1.,0.));
#1681=VECTOR('',#1680,1.);
#1682=CARTESIAN_POINT('',(-4.82833647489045,0.,0.635662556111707));
#1683=LINE('',#1682,#1681);
#1684=EDGE_CURVE('E443',#363,#526,#1683,.T.);
#1685=ORIENTED_EDGE('',*,*,#1684,.F.);
#1686=ORIENTED_EDGE('',*,*,#364,.F.);
#1687=DIRECTION('',(0.,-1.,0.));
#1688=VECTOR('',#1687,1.);
#1689=CARTESIAN_POINT('',(-4.383,0.,0.));
#1690=LINE('',#1689,#1688);
#1691=EDGE_CURVE('E437',#355,#534,#1690,.T.);
#1692=ORIENTED_EDGE('',*,*,#1691,.T.);
#1693=EDGE_LOOP('',(#1679,#1685,#1686,#1692));
#1694=FACE_BOUND('',#1693,.T.);
#1695=ADVANCED_FACE('F973',(#1694),#1678,.F.);
#1696=CARTESIAN_POINT('',(-4.383,0.,0.));
#1697=DIRECTION('',(0.81900626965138,0.,-0.573784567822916));
#1698=DIRECTION('',(-0.573784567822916,0.,-0.81900626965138));
#1699=AXIS2_PLACEMENT_3D('',#1696,#1697,#1698);
#1700=PLANE('',#1699);
#1701=ORIENTED_EDGE('',*,*,#543,.T.);
#1702=ORIENTED_EDGE('',*,*,#1691,.F.);
#1703=ORIENTED_EDGE('',*,*,#356,.F.);
#1704=ORIENTED_EDGE('',*,*,#1650,.T.);
#1705=EDGE_LOOP('',(#1701,#1702,#1703,#1704));
#1706=FACE_BOUND('',#1705,.T.);
#1707=ADVANCED_FACE('F978',(#1706),#1700,.F.);
#1708=CARTESIAN_POINT('',(-4.49929332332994,0.,1.86366831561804));
#1709=DIRECTION('',(0.939605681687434,0.,0.342258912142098));
#1710=DIRECTION('',(0.342258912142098,0.,-0.939605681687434));
#1711=AXIS2_PLACEMENT_3D('',#1708,#1709,#1710);
#1712=PLANE('',#1711);
#1713=ORIENTED_EDGE('',*,*,#519,.T.);
#1714=DIRECTION('',(0.,-1.,0.));
#1715=VECTOR('',#1714,1.);
#1716=CARTESIAN_POINT('',(-4.49929332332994,0.,1.86366831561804));
#1717=LINE('',#1716,#1715);
#1718=EDGE_CURVE('E426',#379,#510,#1717,.T.);
#1719=ORIENTED_EDGE('',*,*,#1718,.F.);
#1720=ORIENTED_EDGE('',*,*,#380,.F.);
#1721=DIRECTION('',(0.,-1.,0.));
#1722=VECTOR('',#1721,1.);
#1723=CARTESIAN_POINT('',(-4.23365289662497,0.,1.1344038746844));
#1724=LINE('',#1723,#1722);
#1725=EDGE_CURVE('E421',#371,#518,#1724,.T.);
#1726=ORIENTED_EDGE('',*,*,#1725,.T.);
#1727=EDGE_LOOP('',(#1713,#1719,#1720,#1726));
#1728=FACE_BOUND('',#1727,.T.);
#1729=ADVANCED_FACE('F981',(#1728),#1712,.F.);
#1730=CARTESIAN_POINT('',(-4.23365289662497,0.,1.1344038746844));
#1731=DIRECTION('',(0.642592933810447,0.,-0.766207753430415));
#1732=DIRECTION('',(-0.766207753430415,0.,-0.642592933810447));
#1733=AXIS2_PLACEMENT_3D('',#1730,#1731,#1732);
#1734=PLANE('',#1733);
#1735=ORIENTED_EDGE('',*,*,#527,.T.);
#1736=ORIENTED_EDGE('',*,*,#1725,.F.);
#1737=ORIENTED_EDGE('',*,*,#372,.F.);
#1738=ORIENTED_EDGE('',*,*,#1684,.T.);
#1739=EDGE_LOOP('',(#1735,#1736,#1737,#1738));
#1740=FACE_BOUND('',#1739,.T.);
#1741=ADVANCED_FACE('F990',(#1740),#1734,.F.);
#1742=CARTESIAN_POINT('',(-3.86363076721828,0.,2.96466815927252));
#1743=DIRECTION('',(0.996172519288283,0.,0.0874088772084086));
#1744=DIRECTION('',(0.0874088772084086,0.,-0.996172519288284));
#1745=AXIS2_PLACEMENT_3D('',#1742,#1743,#1744);
#1746=PLANE('',#1745);
#1747=ORIENTED_EDGE('',*,*,#503,.T.);
#1748=DIRECTION('',(0.,-1.,0.));
#1749=VECTOR('',#1748,1.);
#1750=CARTESIAN_POINT('',(-3.86363076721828,0.,2.96466815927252));
#1751=LINE('',#1750,#1749);
#1752=EDGE_CURVE('E415',#395,#494,#1751,.T.);
#1753=ORIENTED_EDGE('',*,*,#1752,.F.);
#1754=ORIENTED_EDGE('',*,*,#396,.F.);
#1755=DIRECTION('',(0.,-1.,0.));
#1756=VECTOR('',#1755,1.);
#1757=CARTESIAN_POINT('',(-3.79578934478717,0.,2.19150000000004));
#1758=LINE('',#1757,#1756);
#1759=EDGE_CURVE('E407',#387,#502,#1758,.T.);
#1760=ORIENTED_EDGE('',*,*,#1759,.T.);
#1761=EDGE_LOOP('',(#1747,#1753,#1754,#1760));
#1762=FACE_BOUND('',#1761,.T.);
#1763=ADVANCED_FACE('F988',(#1762),#1746,.F.);
#1764=CARTESIAN_POINT('',(-3.79578934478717,0.,2.19150000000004));
#1765=DIRECTION('',(0.422387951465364,0.,-0.906415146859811));
#1766=DIRECTION('',(-0.906415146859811,0.,-0.422387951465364));
#1767=AXIS2_PLACEMENT_3D('',#1764,#1765,#1766);
#1768=PLANE('',#1767);
#1769=ORIENTED_EDGE('',*,*,#511,.T.);
#1770=ORIENTED_EDGE('',*,*,#1759,.F.);
#1771=ORIENTED_EDGE('',*,*,#388,.F.);
#1772=ORIENTED_EDGE('',*,*,#1718,.T.);
#1773=EDGE_LOOP('',(#1769,#1770,#1771,#1772));
#1774=FACE_BOUND('',#1773,.T.);
#1775=ADVANCED_FACE('F995',(#1774),#1768,.F.);
#1776=CARTESIAN_POINT('',(-2.96466815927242,0.,3.86363076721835));
#1777=DIRECTION('',(0.984851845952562,0.,-0.173397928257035));
#1778=DIRECTION('',(-0.173397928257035,0.,-0.984851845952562));
#1779=AXIS2_PLACEMENT_3D('',#1776,#1777,#1778);
#1780=PLANE('',#1779);
#1781=ORIENTED_EDGE('',*,*,#487,.T.);
#1782=DIRECTION('',(0.,-1.,0.));
#1783=VECTOR('',#1782,1.);
#1784=CARTESIAN_POINT('',(-2.96466815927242,0.,3.86363076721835));
#1785=LINE('',#1784,#1783);
#1786=EDGE_CURVE('E399',#411,#478,#1785,.T.);
#1787=ORIENTED_EDGE('',*,*,#1786,.F.);
#1788=ORIENTED_EDGE('',*,*,#412,.F.);
#1789=DIRECTION('',(0.,-1.,0.));
#1790=VECTOR('',#1789,1.);
#1791=CARTESIAN_POINT('',(-3.0992490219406,0.,3.09924902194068));
#1792=LINE('',#1791,#1790);
#1793=EDGE_CURVE('E391',#403,#486,#1792,.T.);
#1794=ORIENTED_EDGE('',*,*,#1793,.T.);
#1795=EDGE_LOOP('',(#1781,#1787,#1788,#1794));
#1796=FACE_BOUND('',#1795,.T.);
#1797=ADVANCED_FACE('F997',(#1796),#1780,.F.);
#1798=CARTESIAN_POINT('',(-3.0992490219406,0.,3.09924902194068));
#1799=DIRECTION('',(0.173397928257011,0.,-0.984851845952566));
#1800=DIRECTION('',(-0.984851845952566,0.,-0.173397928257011));
#1801=AXIS2_PLACEMENT_3D('',#1798,#1799,#1800);
#1802=PLANE('',#1801);
#1803=ORIENTED_EDGE('',*,*,#495,.T.);
#1804=ORIENTED_EDGE('',*,*,#1793,.F.);
#1805=ORIENTED_EDGE('',*,*,#404,.F.);
#1806=ORIENTED_EDGE('',*,*,#1752,.T.);
#1807=EDGE_LOOP('',(#1803,#1804,#1805,#1806));
#1808=FACE_BOUND('',#1807,.T.);
#1809=ADVANCED_FACE('F1005',(#1808),#1802,.F.);
#1810=CARTESIAN_POINT('',(-1.86366831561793,0.,4.49929332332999));
#1811=DIRECTION('',(0.906415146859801,0.,-0.422387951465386));
#1812=DIRECTION('',(-0.422387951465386,0.,-0.906415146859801));
#1813=AXIS2_PLACEMENT_3D('',#1810,#1811,#1812);
#1814=PLANE('',#1813);
#1815=ORIENTED_EDGE('',*,*,#471,.T.);
#1816=DIRECTION('',(0.,-1.,0.));
#1817=VECTOR('',#1816,1.);
#1818=CARTESIAN_POINT('',(-1.86366831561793,0.,4.49929332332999));
#1819=LINE('',#1818,#1817);
#1820=EDGE_CURVE('E379',#427,#462,#1819,.T.);
#1821=ORIENTED_EDGE('',*,*,#1820,.F.);
#1822=ORIENTED_EDGE('',*,*,#428,.F.);
#1823=DIRECTION('',(0.,-1.,0.));
#1824=VECTOR('',#1823,1.);
#1825=CARTESIAN_POINT('',(-2.19149999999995,0.,3.79578934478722));
#1826=LINE('',#1825,#1824);
#1827=EDGE_CURVE('E374',#419,#470,#1826,.T.);
#1828=ORIENTED_EDGE('',*,*,#1827,.T.);
#1829=EDGE_LOOP('',(#1815,#1821,#1822,#1828));
#1830=FACE_BOUND('',#1829,.T.);
#1831=ADVANCED_FACE('F1008',(#1830),#1814,.F.);
#1832=CARTESIAN_POINT('',(-2.19149999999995,0.,3.79578934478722));
#1833=DIRECTION('',(-0.087408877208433,0.,-0.996172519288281));
#1834=DIRECTION('',(-0.996172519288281,0.,0.087408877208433));
#1835=AXIS2_PLACEMENT_3D('',#1832,#1833,#1834);
#1836=PLANE('',#1835);
#1837=ORIENTED_EDGE('',*,*,#479,.T.);
#1838=ORIENTED_EDGE('',*,*,#1827,.F.);
#1839=ORIENTED_EDGE('',*,*,#420,.F.);
#1840=ORIENTED_EDGE('',*,*,#1786,.T.);
#1841=EDGE_LOOP('',(#1837,#1838,#1839,#1840));
#1842=FACE_BOUND('',#1841,.T.);
#1843=ADVANCED_FACE('F1013',(#1842),#1836,.F.);
#1844=CARTESIAN_POINT('',(-0.635662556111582,0.,4.82833647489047));
#1845=DIRECTION('',(0.766207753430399,0.,-0.642592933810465));
#1846=DIRECTION('',(-0.642592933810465,0.,-0.766207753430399));
#1847=AXIS2_PLACEMENT_3D('',#1844,#1845,#1846);
#1848=PLANE('',#1847);
#1849=ORIENTED_EDGE('',*,*,#455,.T.);
#1850=ORIENTED_EDGE('',*,*,#1091,.F.);
#1851=ORIENTED_EDGE('',*,*,#60,.F.);
#1852=DIRECTION('',(0.,-1.,0.));
#1853=VECTOR('',#1852,1.);
#1854=CARTESIAN_POINT('',(-1.13440387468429,0.,4.233652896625));
#1855=LINE('',#1854,#1853);
#1856=EDGE_CURVE('E339',#57,#452,#1855,.T.);
#1857=ORIENTED_EDGE('',*,*,#1856,.T.);
#1858=EDGE_LOOP('',(#1849,#1850,#1851,#1857));
#1859=FACE_BOUND('',#1858,.T.);
#1860=ADVANCED_FACE('F355',(#1859),#1848,.F.);
#1861=CARTESIAN_POINT('',(-1.13440387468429,0.,4.233652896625));
#1862=DIRECTION('',(-0.342258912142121,0.,-0.939605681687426));
#1863=DIRECTION('',(-0.939605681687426,0.,0.342258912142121));
#1864=AXIS2_PLACEMENT_3D('',#1861,#1862,#1863);
#1865=PLANE('',#1864);
#1866=ORIENTED_EDGE('',*,*,#463,.T.);
#1867=ORIENTED_EDGE('',*,*,#1856,.F.);
#1868=ORIENTED_EDGE('',*,*,#434,.F.);
#1869=ORIENTED_EDGE('',*,*,#1820,.T.);
#1870=EDGE_LOOP('',(#1866,#1867,#1868,#1869));
#1871=FACE_BOUND('',#1870,.T.);
#1872=ADVANCED_FACE('F341',(#1871),#1865,.F.);
#1873=CLOSED_SHELL('',(#46,#441,#844,#864,#884,#904,#924,#952,#980,#992,#1012,#1024,#1044,#1056,
#1078,#1095,#1117,#1129,#1151,#1163,#1185,#1197,#1219,#1231,#1253,#1265,#1287,#1299,#1321,#1333,
#1355,#1367,#1389,#1401,#1423,#1435,#1457,#1469,#1491,#1503,#1525,#1537,#1559,#1571,#1593,#1605,
#1627,#1639,#1661,#1673,#1695,#1707,#1729,#1741,#1763,#1775,#1797,#1809,#1831,#1843,#1860,#1872));
#1874=MANIFOLD_SOLID_BREP('B2',#1873);
#1875=ADVANCED_BREP_SHAPE_REPRESENTATION('',(#18,#1874),#14);
#1876=SHAPE_DEFINITION_REPRESENTATION(#9,#1875);
ENDSEC;
END-ISO-10303-21;
